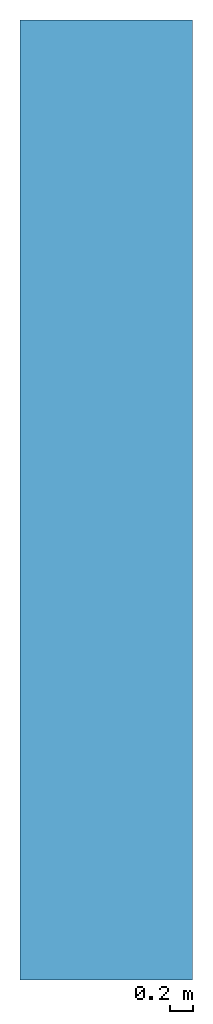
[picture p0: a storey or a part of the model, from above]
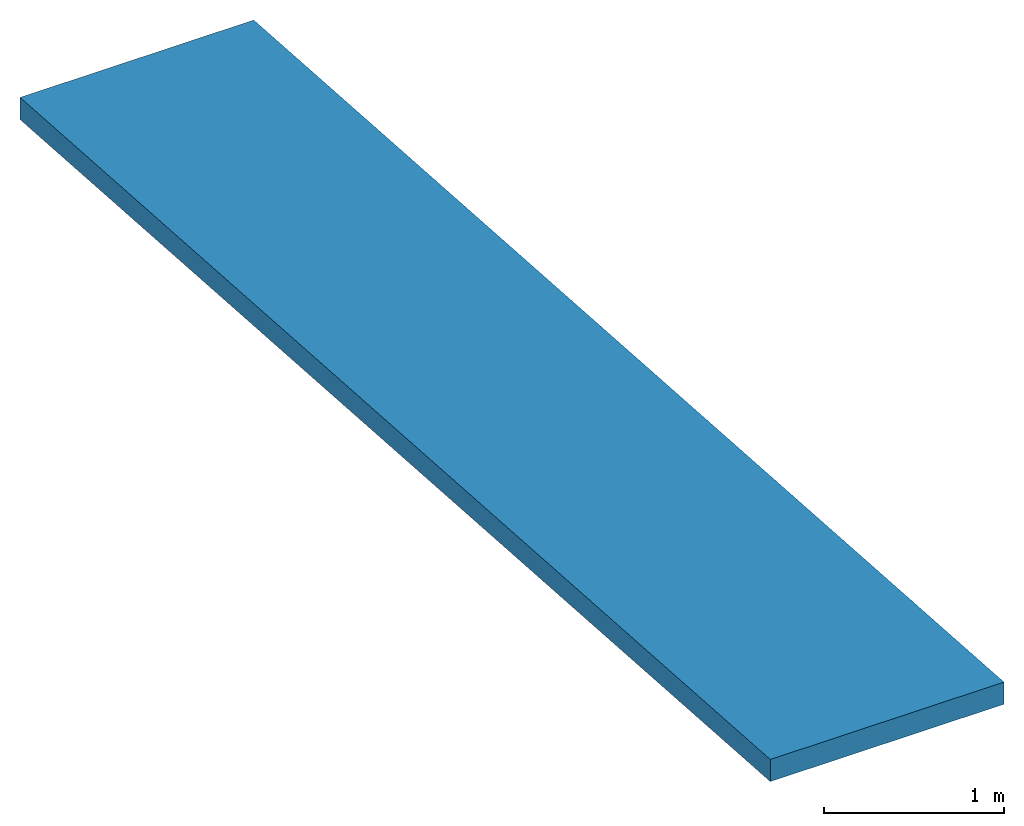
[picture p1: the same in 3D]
Properties of the parts of a building model (IFC2X3), part 1 of 3

# File
Description: ViewDefinition [CoordinationView_V2.0]
File name: Numéro du projet
Time: 2016-10-14T11:20:03
Written by: The EXPRESS Data Manager Version 5.02.0100.07 : 28 Aug 2013
Made in: 20140905_0730(x64) - Exporter 15.7.0.0 - Interface alternative d'export 15.7.0.0
Comment: STEP Physical File produced by: The EXPRESS Data Manager Version 5.02.0100.07 : 28 Aug 2013 * Module: EDMstepFileFactory/EDMstandAlone * Creation date: Fri Oct 14 11:20:03 2016 * Host: Mu-11 * Database: C:\Users\UTILIS~1\AppData\Local\Temp\{3E19F668-D2DF-4540-B0BE-C218E94157A1}\ifc * Database version: 5507 * Database creation date: Fri Oct 14 11:19:26 2016 * Schema: IFC2X3 * Model: DataRepository.ifc * Model creation date: Fri Oct 14 11:19:26 2016 * Header model: DataRepository.ifc_HeaderModel * Header model creation date: Fri Oct 14 11:19:26 2016 * EDMuser: sdai-user * EDMgroup: sdai-group * License ID and type: 5605 : Permanent license. Expiry date: * EDMstepFileFactory options: 020000

# IfcProject, Numéro du projet
LongName: Construction du Pôle Aéronautique au lycée; Phase: DCE

# IfcSite, Default
RefLatitude: 48, 51, 23, 999633; RefLongitude: 2, 21, 3, 553905; RefElevation: 0 cm

# IfcBuilding
Pset_BuildingCommon - NumberOfStoreys: 14

# IfcBuildingStorey (13)
Name | LongName | Elevation (cm)
-77 | -77 | -77
RDC | RDC | -8.82466e-11
vestiaires | vestiaires | 30
R+1 | R+1 | 343
Toiture E1 | Toiture E1 | 373
Acrotère E1 | Acrotère E1 | 410
Acrotère EXT1 | Acrotère EXT1 | 451
Toiture E2 | Toiture E2 | 715
Acrotère E2 | Acrotère E2 | 722
724 | 724 | 724
Acrotère E3 | Acrotère E3 | 801
814 | 814 | 814
Acrotère EXT2 | Acrotère EXT2 | 855

# IfcSpace (77)
InteriorOrExteriorSpace: INTERNAL
Name | In | LongName | Reference | CeilingCovering | WallCovering | FloorCovering
001 | RDC | Sas Hall | Sas Hall 001 | plaf. dalles 60x60 | mur. TV+peinture | sol. existant non modifié carrelage
026 | RDC | Bureau accueil | Bureau accueil 026 | plaf. existant non modifié dalles 60x60 | mur. TV+peinture | sol. existant non modifié moquette
025 | RDC | Réunion | Réunion 025 | plaf. existant non modifié dalles 60x60 | mur. TV+peinture | sol. existant non modifié moquette
014 | RDC | Chaufferie | Chaufferie 014 | plaf. existant non modifié flocage | mur. existant non modifié parpaing | sol. existant non modifié dalle béton
017 | RDC | Travail enseignants | Travail enseignants 017 | plaf. dalles 60x60 | mur. peinture | sol. existant non modifié dalle béton
005 | R+1 | EG/FC | EG/FC 005 | plaf. dalles 60x60 | mur. peinture | sol. pvc
002 | R+1 | Palier 01 R+1 | Palier 01 R+1 002 | dalles fibres bois 120x60 | TV+peinture | sol. pvc
009 | R+1 | Toiture Terrasse | Toiture Terrasse 009
038 | RDC | Travail élèves | Travail élèves 038 | plaf. dalles 60x60 | mur. peinture | sol. existant non modifié dalle béton
039 | RDC | Dgmt sanit. eleve | Dgmt sanit. eleve 039 | plaf. dalles 60x60 | mur. peinture | sol. carrelage
043 | RDC | Vest. H Profs | Vest. H Profs 043 | plaf. dalles 60x60 | mur. faïence | sol. carrelage
046 | RDC | Ménage | Ménage 046 | plaf. existant non modifié plâtre + peinture neuve | mur. peinture + faïence | sol. carrelage
047 | RDC | TP avionique | TP avionique 047 | plaf. dalles 60x60 | mur. peinture | sol. dalle béton
048 | RDC | TP électricité | TP électricité 048 | plaf. dalles 60x60 | mur. peinture | dalle béton + traitement surface
049 | RDC | TP moteur | TP moteur 049 | plaf. dalles 60x60 | mur. peinture | dalle béton + traitement surface
050 | RDC | Grand magasin | Grand magasin 050 | plaf. dalles 60x60 | mur. peinture | dalle béton + traitement surface
051 | RDC | Petit magasin | Petit magasin 051 | plaf. dalles 60x60 | mur. peinture | dalle béton + traitement surface
053 | RDC | Cours composite | Cours composite 053 | plaf. dalles 60x60 | mur. peinture | dalle béton + traitement surface
054 | RDC | TP structure composite | TP structure composite 054 | plaf. dalles 60x60 | mur. peinture | dalle béton + traitement surface
055 | RDC | TP structure métal 02 | TP structure métal 02 055 | plaf. dalles 60x60 | mur. peinture | dalle béton + traitement surface
056 | RDC | TP structure métal 01 | TP structure métal 01 056 | plaf. dalles 60x60 | mur. peinture | dalle béton + traitement surface
057 | RDC | Sas/Dgmt | Sas/Dgmt 057 | plaf. dalles 60x60 | mur. peinture | dalle béton + traitement surface
059 | RDC | Déchets dang. | Déchets dang. 059 | plaf. dalle béton apparente | mur. peinture | dalle béton + traitement surface
060 | RDC | Palier RDC Esc. | Palier RDC Esc. 060 | plaf. dalle béton apparente | mur. peinture | dalle béton + traitement surface
061 | RDC | Sas métal | Sas métal 061 | plaf. dalles 60x60 | mur. peinture | dalle béton + traitement surface
062 | RDC | Sas composite | Sas composite 062 | plaf. dalles 60x60 | mur. peinture | dalle béton + traitement surface
063 | RDC | Sas av./élec. | Sas av./élec. 063 | plaf. dalles 60x60 | mur. peinture | dalle béton + traitement surface
064 | R+1 | Salle classe 03 | Salle classe 03 064 | plaf. dalles 60x60 | mur. peinture | sol. pvc
065 | R+1 | Salle classe 04 | Salle classe 04 065 | plaf. dalles 60x60 | mur. peinture | sol. pvc
066 | R+1 | CAO/DAO | CAO/DAO 066 | plaf. dalles 60x60 | mur. peinture | sol. pvc
069 | R+1 | Local tech. 02 | Local tech. 02 069 | plaf. fibre de bois | mur. fibre de bois + peinture | dalle béton + traitement surface
071 | R+1 | Local tech. 01 | Local tech. 01 071 | plaf. fibre de bois | mur. fibre de bois + peinture | dalle béton + traitement surface
073 | RDC | Stock. prdts dang. | Stock. prdts dang. 073 | plaf. dalle béton apparente | mur. peinture | dalle béton + traitement surface
075 | RDC | Mach. asc. | Mach. asc. 075 | plaf. existant non modifié flocage | mur. existant non modifié parpaing | sol. existant non modifié dalle béton
076 | R+1 | Local tech. 03 | Local tech. 03 076 | plaf. bac acier | mur. peinture | sol. peinture sur plancher collaborant
078 | RDC | Vest. H Elèves 01 | Vest. H Elèves 01 078 | dalles fibres bois 60x60 | peinture sur plâtre | sol. existant non modifié dalle béton
079 | RDC | Vest. H Elèves 02 | Vest. H Elèves 02 079 | dalles fibres bois 60x60 | peinture sur plâtre | sol. pvc
080 | RDC | Vest. H Elèves 03 | Vest. H Elèves 03 080 | dalles fibres bois 60x60 | peinture sur plâtre | sol. pvc
081 | RDC | Vest. H Elèves 04 | Vest. H Elèves 04 081 | dalles fibres bois 60x60 | peinture sur plâtre | sol. pvc
083 | RDC | Atelier aéronefs extension | Atelier aéronefs extension 083 | plateaux perforés | bardage métal + peinture | dalle béton + traitement surface
087 | R+1 | Circu. R+1 Esc. | Circu. R+1 Esc. 087 | dalles fibres bois 120x60 | mur. peinture | sol. pvc
090 | R+1 | Circu. 01 R+1 | Circu. 01 R+1 090 | bac acier perforé existant | mur. peinture + panneaux fibres de bois | sol. pvc
091 | R+1 | Circu. 02 R+1 | Circu. 02 R+1 091 | bac acier perforé existant | garde-corps métalliques | sol. pvc
093 | R+1 | Circu. 04 R+1 | Circu. 04 R+1 093 | dalles fibres bois 120x60 | mur. peinture | sol. pvc
099 | RDC | Vest. H Elèves 05 | Vest. H Elèves 05 099 | dalles fibres bois 60x60 | peinture sur plâtre | sol. pvc
104 | vestiaires | Vest. H Elèves 04 | Vest. H Elèves 04 104 | plaf. dalles 60x60 | mur. peinture | sol. existant non modifié dalle béton
107 | vestiaires | Vest. H Elèves 03 | Vest. H Elèves 03 107 | plaf. dalles 60x60 | mur. peinture | sol. existant non modifié dalle béton
108 | vestiaires | Vest. H Elèves 02 | Vest. H Elèves 02 108 | plaf. dalles 60x60 | mur. peinture | sol. existant non modifié dalle béton
109 | vestiaires | Vest. H Elèves 01 | Vest. H Elèves 01 109 | plaf. dalles 60x60 | mur. peinture | sol. existant non modifié dalle béton
110 | vestiaires | Vest. F Elèves | Vest. F Elèves 110 | plaf. dalles 60x60 | mur. peinture | sol. existant non modifié dalle béton
118 | vestiaires | Sanit. H élèves 02 | Sanit. H élèves 02 118 | plaf. dalles 60x60 | mur. peinture + faïence | sol. existant non modifié dalle béton
082 | RDC | Sanit. H élèves 01 | Sanit. H élèves 01 082 | plaf. dalles 60x60 | mur. faïence | sol. carrelage
084 | RDC | Sanit. F élèves | Sanit. F élèves 084 | plaf. dalles 60x60 | mur. faïence | sol. carrelage
088 | R+1 | Local compresseur | Local compresseur 088 | plaf. fibre de bois | mur. fibre de bois | dalle béton + traitement surface
089 | RDC | Atelier aéronefs existant | Atelier aéronefs existant 089 | plaf. bac acier perforé existant | mur. bardage métal existant + peinture | sol. existant non modifié dalle béton
094 | RDC | Circu. 03 Atelier RDC | Circu. 03 Atelier RDC 094 |  | mur. medium teinté perforé + panneaux fibres de bois | dalle béton + traitement surface
097 | RDC | Circu. 02 Atelier RDC | Circu. 02 Atelier RDC 097 | dalles fibres bois 120x60 | mur. medium teinté perforé + panneaux fibres de bois | dalle béton + traitement surface
100 | RDC | Salle profs. | Salle profs. 100 | plaf. dalles 60x60 | mur. peinture | sol. dalle béton
101 | RDC | Doc. tech. | Doc. tech. 101 | plaf. dalles 60x60 | mur. peinture | sol. dalle béton
102 | RDC | Vie des élèves | Vie des élèves 102 | plaf. dalles 60x60 | mur. peinture | sol. existant non modifié dalle béton
103 | RDC | Vest. F Profs | Vest. F Profs 103 | plaf. dalles 60x60 | mur. faïence | sol. carrelage
105 | RDC | Info. | Info. 105 | plaf. placo |  | sol. carrelage
106 | RDC | Hall/Accueil | Hall/Accueil 106 | plaf. dalles 60x60 inchangées | mur. TV+peinture | sol. existant non modifié carrelage
116 | RDC | Circu. 01 Atelier RDC | Circu. 01 Atelier RDC 116 | dalles fibres bois 120x60 | mur. peinture | sol. existant non modifié dalle béton
117 | R+1 | ACT/maint. virt | ACT/maint. virt 117 | plaf. dalles 60x60 | mur. peinture | sol. pvc
120 | R+1 | Salle classe 01 | Salle classe 01 120 | plaf. dalles 60x60 | mur. peinture | sol. pvc
121 | R+1 | Salle de classe 02 | Salle de classe 02 121 | plaf. dalles 60x60 | mur. peinture | sol. pvc
122 | R+1 | Circu 03 R+1 | Circu 03 R+1 122 | plaf. charpente | mur. panneaux fibre de bois | sol. pvc
124 | R+1 | Placard 02 | Placard 02 124 | plaf. dalles 60x60 | mur. peinture | sol. pvc
125 | RDC | Placard elec 01 | Placard elec 01 125 | plaf. peinture | mur. peinture | sol. dalle béton
126 | RDC | Local déchet | Local déchet 126 | bac acier | treillis soudé | sol. dalle béton
127 | RDC | Circulation vestiaire | Circulation vestiaire 127
128 | RDC | Pl. TP elec | Pl. TP elec 128 | plaf. peinture
129 | RDC | Cfa 01 | Cfa 01 129
130 | RDC | Cfa 01 | Cfa 01 130 | plaf. peinture
131 | R+1 | Pl. Elec. 03 | Pl. Elec. 03 131 | plaf. placo
132 | R+1 | Pièce | Pièce 132 | dalles fibres bois 120x60

# IfcBeam: IPE-Poutrelles_240:IPE240:577120 (2)
In: RDC
Material: Métal - Acier - 345 MPa
Pset_BeamCommon - LoadBearing: yes; IsExternal: no; Reference: IPE240; Span: 633.9 cm; Slope: 2.19531 deg
Name (IPE-Poutrelles_240:IPE240:...)
589190
768656

# IfcBuildingElementProxy: 1000 x 800 mm (3)
In: Acrotère E1
Type - Material: Acier - Galvanisé
Pset_BuildingElementProxyCommon - Reference: 1000 x 800 mm
Name (Grille d'aération-100x80:1000 x 800 mm:...)
1417437
1754409
1755015

# IfcBuildingElementProxy: 1700 x 800 mm (4)
Type - Material: Acier - Galvanisé
Pset_BuildingElementProxyCommon - Reference: 1700 x 800 mm
Name (Grille d'aération-100x80:1700 x 800 mm:...) | In
1752096 | Acrotère E1
1881553 | RDC
1881798 | vestiaires
2003831 | Acrotère E1

# IfcBuildingElementProxy: 200 x 200 mm (3)
Type - Material: Acier - Galvanisé
Pset_BuildingElementProxyCommon - Reference: 200 x 200 mm
Name (Grille d'aération 20x20- Mur:200 x 200 mm:...) | In
1395204 | vestiaires
2146164 | Acrotère E1
2171006 | 056

# IfcBuildingElementProxy: 310x400, Grille d'aération-100x80:310x400:1752675
In: RDC
Type - Material: Acier - Galvanisé
Pset_BuildingElementProxyCommon - Reference: 310x400

# IfcBuildingElementProxy: 600mm, Echelle à crinoline - 02:600mm:1773401
In: R+1
Type - Material: Métal - Aluminium
Pset_BuildingElementProxyCommon - Reference: 600mm

# IfcBuildingElementProxy: 900 x 600 mm, Grille d'aération-100x20:900 x 600 mm:1754410
In: Acrotère E1
Type - Material: Acier - Galvanisé
Pset_BuildingElementProxyCommon - Reference: 900 x 600 mm

# IfcBuildingElementProxy: Banc_Moshi_235cm, Banc_Moshi_235cm:Banc_Moshi_235cm:1062523
In: 053
Type - Material: polantis metal, polantis wood
Pset_BuildingElementProxyCommon - Reference: Banc_Moshi_235cm

# IfcBuildingElementProxy: Garde-corps_R+1-esc-1, Garde-corps_R+1-esc-1:Garde-corps_R+1-esc-1:2020194
In: 087
Pset_BuildingElementProxyCommon - Reference: Garde-corps_R+1-esc-1

# IfcBuildingElementProxy: Multi-cyclone, Multi-cyclone:Multi-cyclone:669395
In: R+1
Type - Material: Forme par défaut
Pset_BuildingElementProxyCommon - Reference: Multi-cyclone

# IfcBuildingElementProxy: Ordinateur Mac (23)
Type - Material: Plastique - Blanc brillant, Métal - Aluminium satiné, Verre - Noir brillant
Pset_BuildingElementProxyCommon - Reference: Ordinateur Mac
Name (Ordinateur Mac:Ordinateur Mac:...) | In
1072757 | 102
1073011 | 102
1073091 | 102
1073150 | 102
1073151 | 102
1092645 | 089
1092646 | 089
1092986 | 089
1092987 | 089
1093031 | 089
1093032 | 089
1093033 | 089
1093034 | 089
1093087 | 089
1093088 | 089
1093089 | 089
1093090 | 089
1093091 | 089
1093092 | 089
1093093 | 089
1093094 | 089
1528579 | 050
1528580 | 050

# IfcBuildingElementProxy: Portique_1-2 (2)
In: RDC
Pset_BuildingElementProxyCommon - Reference: Portique_1-2
Name (Portique_11:Portique_1-2:...)
776761
776763

# IfcBuildingElementProxy: Portique_3, Portique_3:Portique_3:603496
In: RDC
Pset_BuildingElementProxyCommon - Reference: Portique_3

# IfcBuildingElementProxy: Portique_3 2, Portique_1:Portique_3 2:768664
In: RDC
Pset_BuildingElementProxyCommon - Reference: Portique_3 2

# IfcBuildingElementProxy: Portique_4-5-6 2 (3)
In: RDC
Pset_BuildingElementProxyCommon - Reference: Portique_4-5-6 2
Name (Portique_4-51:Portique_4-5-6 2:...)
768658
768660
768662

# IfcBuildingElementProxy: Portique_D-E-G (3)
In: RDC
Pset_BuildingElementProxyCommon - Reference: Portique_D-E-G
Name (Portique_D-E-G:Portique_D-E-G:...)
768680
768682
768684

# IfcBuildingElementProxy: Portique_H, Portique_H:Portique_H:768678
In: RDC
Pset_BuildingElementProxyCommon - Reference: Portique_H

# IfcBuildingElementProxy: Profil en relief:Plinthe-10x2 (5)
Pset_BuildingElementProxyCommon - Reference: Plinthe-10x2
Name (Profil en relief:...) | In
3 x Plinthe-10x2 | RDC
2 x Plinthe-10x2 | R+1

# IfcBuildingElementProxy: Profil en relief:Plinthe-carrelage-30x10
In: RDC
Pset_BuildingElementProxyCommon - Reference: Plinthe-carrelage-30x10

# IfcBuildingElementProxy: Profil en relief:Profil en relief
In: RDC
Pset_BuildingElementProxyCommon - Reference: Profil en relief

# IfcBuildingElementProxy: Profil en relief:Profil-acier-5x5 (28)
Pset_BuildingElementProxyCommon - Reference: Profil-acier-5x5
Name (Profil en relief:...) | In
10 x Profil-acier-5x5 | R+1
18 x Profil-acier-5x5 | RDC

# IfcBuildingElementProxy: Profil en relief:profil-couvertine (4)
Pset_BuildingElementProxyCommon - Reference: profil-couvertine
Name (Profil en relief:...) | In
3 x profil-couvertine | R+1
profil-couvertine | RDC

# IfcBuildingElementProxy: Profil en relief:profil-couvertine-ex (9)
Pset_BuildingElementProxyCommon - Reference: profil-couvertine-ex
Name (Profil en relief:...) | In
7 x profil-couvertine-ex | RDC
profil-couvertine-ex | R+1
profil-couvertine-ex | Toiture E1

# IfcBuildingElementProxy: descenteEP (10)
Pset_BuildingElementProxyCommon - Reference: descenteEP
Name (descenteEP:descenteEP:...) | In
1228838 | R+1
1229246 | R+1
1229569 | R+1
1229680 | R+1
1229801 | R+1
1230112 | R+1
1230804 | R+1
1231167 | R+1
1900189 | Acrotère E3
1900580 | Acrotère E2

# IfcBuildingElementProxy: ensemble-Garde-corps_R+1, ensemble-Garde-corps_R+1:ensemble-Garde-corps_R+1:1492431
In: R+1
Pset_BuildingElementProxyCommon - Reference: ensemble-Garde-corps_R+1

# IfcBuildingElementProxy: garde-corps-demontable (39)
Pset_BuildingElementProxyCommon - Reference: garde-corps-demontable
Name (garde-corps-demontable:garde-corps-demontable:...) | In
2033946 | 083
2033958 | 083
2034228 | 083
2034236 | 083
2034244 | 083
2034254 | 083
2034264 | 083
2034270 | 083
2034278 | 083
2034288 | 083
2034326 | 083
2034327 | 083
2034382 | 083
2034390 | 083
2034400 | 083
2034412 | 083
2034420 | 083
2034430 | 083
2034442 | 083
2034454 | 083
2034462 | 083
2034472 | 083
2036073 | 083
2036113 | 083
2036123 | 083
2036131 | 083
2036139 | 083
2036147 | 083
2036155 | 083
2036165 | 083
2036177 | 083
2155505 | 089 | Group: Groupe de modèles:Garde-corps:2155973
2155656 | 089 | Group: Groupe de modèles:Garde-corps:2155973
2155762 | 089 | Group: Groupe de modèles:Garde-corps:2155973
2155802 | 089 | Group: Groupe de modèles:Garde-corps:2155973
2155838 | 089 | Group: Groupe de modèles:Garde-corps:2155973
2155874 | 089 | Group: Groupe de modèles:Garde-corps:2155973
2155910 | 089 | Group: Groupe de modèles:Garde-corps:2155973
2155946 | 089 | Group: Groupe de modèles:Garde-corps:2155973

# IfcBuildingElementProxy: parevue-barreau, parevue-barreau:parevue-barreau:1796733
In: 089
Pset_BuildingElementProxyCommon - Reference: parevue-barreau

# IfcBuildingElementProxy: profil-metallique-recouvrement-JD, profil-metallique-recouvrement-JD:profil-metallique-recouvrement-JD:1324721
In: RDC
Type - Material: Montant métallique
Pset_BuildingElementProxyCommon - Reference: profil-metallique-recouvrement-JD

# IfcColumn: Diamètre de 200 mm (8)
In: RDC
Type - ElementType: Diamètre de 200 mm; PredefinedType: COLUMN; Material: Béton, coffrage en contreplaqué
Pset_ColumnCommon - LoadBearing: yes; IsExternal: no; Reference: Diamètre de 200 mm
Name
Poteau porteur rond:Diamètre de 200 mm:336266
Poteau porteur rond:Diamètre de 200 mm:337549
Poteau porteur rond:Diamètre de 200 mm:337617
Poteau porteur rond:Diamètre de 200 mm:337636
Poteau porteur rond:Diamètre de 200 mm:337651
Poteau porteur rond:Diamètre de 200 mm:337666
Poteau porteur rond:Diamètre de 200 mm:337681
Poteau porteur carre:Diamètre de 200 mm:639674

# IfcColumn: Diamètre de 200 mm (2)
In: R+1
Type - ElementType: Diamètre de 200 mm; PredefinedType: COLUMN; Material: Béton, coulé sur place, gris
Pset_ColumnCommon - LoadBearing: yes; IsExternal: no; Reference: Diamètre de 200 mm
Name (Poteau porteur rectangle:Diamètre de 200 mm:...)
1629248
1629738

# IfcColumn: Diamètre de 780 mm, Poteau porteur rond:Diamètre de 780 mm:373323
In: RDC
Type - ElementType: Diamètre de 780 mm; PredefinedType: COLUMN; Material: Maçonnerie - Béton
Pset_ColumnCommon - LoadBearing: yes; IsExternal: no; Reference: Diamètre de 780 mm

# IfcColumn: Diamètre de 800 m, Poteau porteur rond simple:Diamètre de 800 m:2145215
In: vestiaires
Type - ElementType: Diamètre de 800 m; PredefinedType: COLUMN; Material: Béton, coulé sur place
Pset_ColumnCommon - LoadBearing: yes; IsExternal: no; Reference: Diamètre de 800 m

# IfcColumn: HEA160 (9)
In: RDC
Type - ElementType: HEA160; PredefinedType: COLUMN; Material: Acier, 45-345
Pset_ColumnCommon - LoadBearing: yes; IsExternal: no; Reference: HEA160
Name
IPE-240-120:HEA160:768575
IPE-240-120:HEA160:768577
IPE-240-120:HEA160:768603
IPE-240-120:HEA160:768605
IPE-240-120:HEA160:768607
IPE-200-100:HEA160:768611
IPE-200-100:HEA160:768613
IPE-200-100:HEA160:768615
IPE-240-120:HEA160:768668

# IfcColumn: IPE 180 (48)
Type - ElementType: IPE 180; PredefinedType: COLUMN; Material: Acier, 45-345
Pset_ColumnCommon - LoadBearing: yes; IsExternal: no; Reference: IPE 180
Name (IPE-180-90:IPE 180:...) | In
397627 | RDC
400613 | RDC
745833 | R+1
745837 | R+1
745839 | R+1
745843 | R+1
746483 | R+1
746485 | R+1
746487 | R+1
746489 | R+1
768581 | RDC
768583 | RDC
768648 | RDC
1098688 | RDC
1350390 | RDC
1350392 | RDC
1370499 | R+1
1370501 | R+1
1370512 | R+1
1370514 | R+1
1792442 | RDC
1792444 | RDC
1792456 | RDC
1792458 | RDC
1792460 | RDC
1792462 | RDC
1792464 | RDC
1792466 | RDC
1792468 | RDC
1792470 | RDC
1792472 | RDC
1792474 | RDC
1792476 | RDC
1792478 | RDC
1792480 | RDC
1792482 | RDC
1792484 | RDC
1792486 | RDC
1792488 | RDC
1792490 | RDC
1792492 | RDC
1792494 | RDC
1792496 | RDC
1792498 | RDC
1792500 | RDC
1792502 | RDC
1792504 | RDC
1792506 | RDC

# IfcColumn: IPE 270 (2)
In: RDC
Type - ElementType: IPE 270; PredefinedType: COLUMN; Material: Acier, 45-345
Pset_ColumnCommon - LoadBearing: yes; IsExternal: no; Reference: IPE 270
Name (IPE-270-135:IPE 270:...)
400209
768609

# IfcColumn: IPE 300 (7)
Type - ElementType: IPE 300; PredefinedType: COLUMN; Material: Acier, 45-345
Pset_ColumnCommon - LoadBearing: yes; IsExternal: no; Reference: IPE 300
Name (IPE-300-150:IPE 300:...) | In
484381 | R+1
768569 | RDC
768571 | RDC
768573 | RDC
768644 | RDC
768646 | RDC
768650 | R+1

# IfcColumn: IPE 450 (7)
In: RDC
Type - ElementType: IPE 450; PredefinedType: COLUMN; Material: Acier, 45-345
Pset_ColumnCommon - LoadBearing: yes; IsExternal: no; Reference: IPE 450
Name
IPE-450-190:IPE 450:768585
IPE-450-190:IPE 450:768587
IPE-450-190:IPE 450:768597
IPE-450-190:IPE 450:768601
IPE-96-100:IPE 450:768670
IPE-450-190:IPE 450:1098042
IPE-450-190:IPE 450:1098044

# IfcColumn: IPE200 (4)
In: RDC
Type - ElementType: IPE200; PredefinedType: COLUMN; Material: Acier, 45-345
Pset_ColumnCommon - LoadBearing: yes; IsExternal: no; Reference: IPE200
Name (IPE-200-100:IPE200:...)
399874
400471
400545
400561

# IfcColumn: IPE240 (2)
In: RDC
Type - ElementType: IPE240; PredefinedType: COLUMN; Material: Acier, 45-345
Pset_ColumnCommon - LoadBearing: yes; IsExternal: no; Reference: IPE240
Name (IPE-240-120:IPE240:...)
387907
397541

# IfcColumn: IPE360 (7)
In: RDC
Type - ElementType: IPE360; PredefinedType: COLUMN; Material: Acier, 45-345
Pset_ColumnCommon - LoadBearing: yes; IsExternal: no; Reference: IPE360
Name (IPE-360-170:IPE360:...)
768563
768565
768567
768589
768591
768593
836311

# IfcCovering: Plafond composé:Pafond-fibre-de-bois, Plafond composé:Pafond-fibre-de-bois:2104556
In: 132
PredefinedType: CEILING; Material: Panneau de fibres à densité moyenne MDF 10 cm
Pset_CoveringCommon - Reference: Pafond-fibre-de-bois; TotalThickness: 10 cm

# IfcCovering: Plafond composé:Plafond 120x60 (3)
PredefinedType: CEILING; Material: Maçonnerie - Isolant 3 cm, Faux-plafond-Trame 60x 60_MU 2 cm
Pset_CoveringCommon - Reference: Plafond 120x60; TotalThickness: 5 cm
Name (Plafond composé:Plafond 120x60:...) | In
993673 | R+1
1398973 | RDC
2018109 | 132

# IfcCovering: Plafond composé:Plafond avec isolation (51)
PredefinedType: CEILING; Material: Maçonnerie - Isolant_MU 5 cm
Pset_CoveringCommon - Reference: Plafond avec isolation; TotalThickness: 5 cm
Name (Plafond composé:Plafond avec isolation:...) | In
992757 | RDC
992784 | RDC
992800 | RDC
992824 | 084
992838 | 084
992854 | 105
992862 | RDC
992885 | RDC
992893 | 103
992904 | RDC
992912 | RDC
992921 | RDC
992931 | RDC
992949 | RDC
992978 | RDC
993002 | RDC
993036 | RDC
993046 | 129
993057 | RDC
993083 | RDC
993117 | RDC
993138 | 118
993146 | 104
993154 | 107
993162 | 109
993170 | 110
993562 | 108
993633 | R+1
993641 | R+1
1398648 | 128
1398947 | RDC
1398959 | RDC
1399494 | RDC
1399507 | RDC
1399522 | RDC
1399539 | 101
1400398 | R+1
1400413 | 121
1400424 | 120
1400432 | 117
1404346 | R+1
1696043 | 097
1771134 | R+1
1772691 | R+1
1775926 | R+1
1778344 | RDC
1825757 | 103
1825768 | 103
1825784 | 103
1854031 | RDC
2046370 | 102

# IfcCovering: Plafond de base:Plafond 600 mm x 600 mm (2)
In: R+1
PredefinedType: CEILING
Pset_CoveringCommon - Reference: Plafond 600 mm x 600 mm
Name (Plafond de base:Plafond 600 mm x 600 mm:...)
993578
993588

# IfcCurtainWall: Mur-rideau:1 m x 1 m - Meneaux, Mur-rideau:1 m x 1 m - Meneaux:782304
In: R+1
Pset_CurtainWallCommon - IsExternal: no; Reference: 1 m x 1 m - Meneaux

# IfcCurtainWall: Mur-rideau:Simple panneau (72)
Pset_CurtainWallCommon - IsExternal: no; Reference: Simple panneau
Name (Mur-rideau:Simple panneau:...) | In | Group
693776 | RDC | Groupe de modèles:mur-rideau-1:696009
703710 | RDC | Groupe de modèles:fc-ouest-men-03:712083
709952 | RDC | Groupe de modèles:porte-pliante-16mX5m:710013
712245 | RDC | Groupe de modèles:fc-ouest-men-05:712792
712561 | RDC | Groupe de modèles:fc-ouest-men-01:712563
714304 | RDC | Groupe de modèles:fc-est-men-01:714451
717006 | RDC
733055 | R+1 | Groupe de modèles:fc-est-men-04:733328
733670 | R+1 | Groupe de modèles:fc-est-men-04:733672
734568 | R+1 | Groupe de modèles:fc-est-men-05:734619
734798 | R+1 | Groupe de modèles:fc-est-men-06:735172
734948 | R+1 | Groupe de modèles:fc-est-men-07:735197
748059 | RDC
750284 | RDC | Groupe de modèles:men-2nd-j-type3:750290
750903 | RDC | Groupe de modèles:men-2nd-j-100:750974
758243 | RDC | Groupe de modèles:men-2nd-j-100:758245
758615 | RDC | Groupe de modèles:imposte-vitree-151cm:758786
759191 | RDC | Groupe de modèles:imposte-vitree-151cm:759193
759770 | RDC | Groupe de modèles:men-2nd-j-type3:759776
759816 | RDC | Groupe de modèles:men-2nd-j-type3:759822
760032 | RDC | Groupe de modèles:men-2nd-j-type5:760064
836055 | R+1 | Groupe de modèles:men-2nd-j-100-hsup:836057
836076 | R+1 | Groupe de modèles:men-2nd-j-100-hsup:836078
836097 | R+1 | Groupe de modèles:men-2nd-j-100-hsup:836099
836132 | R+1 | Groupe de modèles:men-2nd-j-100-hsup:836134
836153 | R+1 | Groupe de modèles:men-2nd-j-100-hsup:836155
836294 | R+1 | Groupe de modèles:imposte-vitree-102cm:836300
891742 | R+1 | Groupe de modèles:imposte-vitree-102cm:891748
968480 | RDC | Groupe de modèles:imposte-vitree-204:968508
1119323 | RDC
1247236 | RDC | Groupe de modèles:imposte-vitree-102cm--:1247272
1282591 | RDC | Groupe de modèles:fc-ouest-men-04:1282593
1284019 | RDC | Groupe de modèles:fc-ouest-men-02:1284021
1284645 | RDC | Groupe de modèles:fc-ouest-men-06:1222254
1292162 | RDC
1360494 | R+1 | Groupe de modèles:shed2:1363791
1362082 | R+1 | Groupe de modèles:shed1-:1363832
1362164 | R+1
1406046 | RDC | Groupe de modèles:fc-ouest-men-04:1406048
1449844 | R+1 | Groupe de modèles:men-2nd-j-100-hsup:1449846
1526731 | RDC | Groupe de modèles:men-2nd-j-100:1526733
1604210 | RDC
1604349 | RDC
1604377 | RDC
1604395 | RDC
1604415 | RDC
1604443 | RDC
1604461 | RDC
1604822 | RDC
1607775 | RDC
1608067 | RDC
1608097 | RDC
1608115 | RDC
1608135 | RDC
1627353 | RDC
1627357 | RDC
1627361 | RDC
1629918 | R+1 | Groupe de modèles:men-2nd-j-100-hsup:1628725
1629927 | R+1 | Groupe de modèles:men-2nd-j-100-hsup:1628718
1631721 | R+1
1631751 | R+1 | Groupe de modèles:men-2nd-j-100-hsup 3:1631753
1631758 | R+1
1657073 | RDC | Groupe de modèles:imposte-vitree-191 2:1657079
1744592 | R+1
1744618 | R+1
1744644 | R+1
1745365 | R+1
1745391 | R+1
1745417 | R+1
1877801 | RDC
1878107 | RDC
1880841 | RDC

# IfcDoor: 1.00m x 2.04m, Coulissante - Apparente:1.00m x 2.04m:1238631
In: RDC
Type - OperationType: SLIDING_TO_LEFT; ParameterTakesPrecedence: no; Sizeable: no; Material: Porte - Poignée, Porte - Cadre, Porte - Panneau
Type - Coulissante - Apparente:1.00m x 2.04m:1238631 - PanelOperation: SLIDING
OverallHeight: 204 cm; OverallWidth: 103 cm
Pset_DoorCommon - IsExternal: no; Reference: 1.00m x 2.04m; ThermalTransmittance: 3.7021 kg/K/s3

# IfcDoor: 123 x 204 cm, Double(R)_bois_mu:123 x 204 cm:1194059
In: RDC
Type - OperationType: DOUBLE_DOOR_SINGLE_SWING; ParameterTakesPrecedence: no; Sizeable: no; Material: Porte - Poignée, Porte - Cadre, Porte - Panneau
Type - Double(R)_bois_mu:123 x 204 cm:1194059 - PanelOperation: SWINGING
OverallHeight: 207 cm; OverallWidth: 129 cm
Pset_DoorCommon - IsExternal: no; Reference: 123 x 204 cm; ThermalTransmittance: 3.7021 kg/K/s3

# IfcDoor: 143 x 204 cm (4)
Type - OperationType: DOUBLE_DOOR_SINGLE_SWING; ParameterTakesPrecedence: no; Sizeable: no; Material: Porte - Poignée, Porte - Cadre, Porte - Panneau
Type - Double(R)_bois_Existant_mu:143 x 204 cm:1601129 - PanelOperation: SWINGING
OverallHeight: 207 cm; OverallWidth: 149 cm
Pset_DoorCommon - IsExternal: no; Reference: 143 x 204 cm; ThermalTransmittance: 3.7021 kg/K/s3
Name (Double(R)_bois_Existant_mu:143 x 204 cm:...) | In
1601129 | RDC
1601223 | RDC
1607774 | RDC
1898730 | R+1

# IfcDoor: 143 x 204 cm (2)
In: RDC
Type - OperationType: DOUBLE_DOOR_SINGLE_SWING; ParameterTakesPrecedence: no; Sizeable: no; Material: Porte - Poignée, Porte - Cadre, Porte - Panneau
Type - Double(R)_bois_Existant_mu:143 x 204 cm:1826486 - PanelOperation: SWINGING
OverallHeight: 207 cm; OverallWidth: 149 cm
Pset_DoorCommon - IsExternal: no; Reference: 143 x 204 cm; ThermalTransmittance: 3.7021 kg/K/s3
Name (Double(R)_bois_Existant_mu:143 x 204 cm:...)
1826486
1826530

# IfcDoor: 143 x 204 cm (12)
Type - ParameterTakesPrecedence: no; Sizeable: no; Material: Aluminium-Dorma Metal-Anodized Silver, Porte - Cadre, Porte - Panneau
OverallHeight: 207 cm; OverallWidth: 149 cm
Pset_DoorCommon - IsExternal: no; Reference: 143 x 204 cm; ThermalTransmittance: 3.7021 kg/K/s3
Name (Tierce(R)_bois_mu:143 x 204 cm:...) | In
654453 | RDC
654565 | RDC
654660 | RDC
662013 | R+1
662110 | R+1
679970 | R+1
736615 | RDC
1241583 | RDC
1351042 | RDC
1631308 | R+1
1694524 | RDC
1811255 | RDC

# IfcDoor: 143 x 241 cm, Tierce(R)_bois_mu:143 x 241 cm:1754408
In: R+1
Type - ParameterTakesPrecedence: no; Sizeable: no; Material: Porte - Poignée, Porte - Cadre, Porte - Panneau
OverallHeight: 244 cm; OverallWidth: 149 cm
Pset_DoorCommon - IsExternal: no; Reference: 143 x 241 cm; ThermalTransmittance: 3.7021 kg/K/s3

# IfcDoor: 163 x 204 cm, Double(R)_bois_Existant_mu:163 x 204 cm:1601128
In: RDC
Type - OperationType: DOUBLE_DOOR_SINGLE_SWING; ParameterTakesPrecedence: no; Sizeable: no; Material: Porte - Poignée, Porte - Cadre, Porte - Panneau
Type - Double(R)_bois_Existant_mu:163 x 204 cm:1601128 - PanelOperation: SWINGING
OverallHeight: 207 cm; OverallWidth: 169 cm
Pset_DoorCommon - IsExternal: no; Reference: 163 x 204 cm; ThermalTransmittance: 3.7021 kg/K/s3

# IfcDoor: 163 x 204 cm, Double(R)_bois_mu:163 x 204 cm:1194466
In: RDC
Type - OperationType: DOUBLE_DOOR_SINGLE_SWING; ParameterTakesPrecedence: no; Sizeable: no; Material: Porte - Poignée, Porte - Cadre, Porte - Panneau
Type - Double(R)_bois_mu:163 x 204 cm:1194466 - PanelOperation: SWINGING
OverallHeight: 207 cm; OverallWidth: 169 cm
Pset_DoorCommon - IsExternal: no; Reference: 163 x 204 cm; ThermalTransmittance: 3.7021 kg/K/s3

# IfcDoor: 163 x 204 cm, Double(R)_bois_mu:163 x 204 cm:1580174
In: RDC
Type - OperationType: DOUBLE_DOOR_SINGLE_SWING; ParameterTakesPrecedence: no; Sizeable: no; Material: Porte - Poignée, Porte - Cadre, Porte - Panneau
Type - Double(R)_bois_mu:163 x 204 cm:1580174 - PanelOperation: SWINGING
OverallHeight: 207 cm; OverallWidth: 169 cm
Pset_DoorCommon - IsExternal: no; Reference: 163 x 204 cm; ThermalTransmittance: 3.7021 kg/K/s3

# IfcDoor: 183 x 204 cm, Double(R)_bois_Existant_mu:183 x 204 cm:1590367
In: RDC
Type - OperationType: DOUBLE_DOOR_SINGLE_SWING; ParameterTakesPrecedence: no; Sizeable: no; Material: Porte - Poignée, Porte - Cadre, Porte - Panneau
Type - Double(R)_bois_Existant_mu:183 x 204 cm:1590367 - PanelOperation: SWINGING
OverallHeight: 207 cm; OverallWidth: 189 cm
Pset_DoorCommon - IsExternal: no; Reference: 183 x 204 cm; ThermalTransmittance: 3.7021 kg/K/s3

# IfcDoor: 183 x 204 cm, Double(R)_bois_mu:183 x 204 cm:652799
In: RDC
Type - OperationType: DOUBLE_DOOR_SINGLE_SWING; ParameterTakesPrecedence: no; Sizeable: no; Material: Porte - Poignée, Porte - Cadre, Porte - Panneau
Type - Double(R)_bois_mu:183 x 204 cm:652799 - PanelOperation: SWINGING
OverallHeight: 207 cm; OverallWidth: 189 cm
Pset_DoorCommon - IsExternal: no; Reference: 183 x 204 cm; ThermalTransmittance: 3.7021 kg/K/s3

# IfcDoor: 183 x 204 cm, Double(R)_bois_mu:183 x 204 cm:652915
In: RDC
Type - OperationType: DOUBLE_DOOR_SINGLE_SWING; ParameterTakesPrecedence: no; Sizeable: no; Material: Porte - Poignée, Porte - Cadre, Porte - Panneau
Type - Double(R)_bois_mu:183 x 204 cm:652915 - PanelOperation: SWINGING
OverallHeight: 207 cm; OverallWidth: 189 cm
Pset_DoorCommon - IsExternal: no; Reference: 183 x 204 cm; ThermalTransmittance: 3.7021 kg/K/s3

# IfcDoor: 183 x 204 cm, Double(R)_bois_mu:183 x 204 cm:652933
In: RDC
Type - OperationType: DOUBLE_DOOR_SINGLE_SWING; ParameterTakesPrecedence: no; Sizeable: no; Material: Porte - Poignée, Porte - Cadre, Porte - Panneau
Type - Double(R)_bois_mu:183 x 204 cm:652933 - PanelOperation: SWINGING
OverallHeight: 207 cm; OverallWidth: 189 cm
Pset_DoorCommon - IsExternal: no; Reference: 183 x 204 cm; ThermalTransmittance: 3.7021 kg/K/s3

# IfcDoor: 183 x 204 cm, Double(R)_bois_mu:183 x 204 cm:654791
In: RDC
Type - OperationType: DOUBLE_DOOR_SINGLE_SWING; ParameterTakesPrecedence: no; Sizeable: no; Material: Porte - Poignée, Porte - Cadre, Porte - Panneau
Type - Double(R)_bois_mu:183 x 204 cm:654791 - PanelOperation: SWINGING
OverallHeight: 207 cm; OverallWidth: 189 cm
Pset_DoorCommon - IsExternal: no; Reference: 183 x 204 cm; ThermalTransmittance: 3.7021 kg/K/s3

# IfcDoor: 183 x 260 cm, Double(R)_bois_Existant_mu:183 x 260 cm:1608468
In: RDC
Type - OperationType: DOUBLE_DOOR_SINGLE_SWING; ParameterTakesPrecedence: no; Sizeable: no; Material: Porte - Poignée, Porte - Cadre, Porte - Panneau
Type - Double(R)_bois_Existant_mu:183 x 260 cm:1608468 - PanelOperation: SWINGING
OverallHeight: 263 cm; OverallWidth: 189 cm
Pset_DoorCommon - IsExternal: no; Reference: 183 x 260 cm; ThermalTransmittance: 3.7021 kg/K/s3

# IfcDoor: 183 x 260 cm, Double(R)_bois_Existant_mu:183 x 260 cm:1608475
In: RDC
Type - OperationType: DOUBLE_DOOR_SINGLE_SWING; ParameterTakesPrecedence: no; Sizeable: no; Material: Porte - Poignée, Porte - Cadre, Porte - Panneau
Type - Double(R)_bois_Existant_mu:183 x 260 cm:1608475 - PanelOperation: SWINGING
OverallHeight: 263 cm; OverallWidth: 189 cm
Pset_DoorCommon - IsExternal: no; Reference: 183 x 260 cm; ThermalTransmittance: 3.7021 kg/K/s3

# IfcDoor: 183 x 280 cm, Double(R)_bois_mu:183 x 280 cm:1058547
In: RDC
Type - OperationType: DOUBLE_DOOR_SINGLE_SWING; ParameterTakesPrecedence: no; Sizeable: no; Material: Porte - Poignée, Porte - Cadre, Porte - Panneau
Type - Double(R)_bois_mu:183 x 280 cm:1058547 - PanelOperation: SWINGING
OverallHeight: 279 cm; OverallWidth: 189 cm
Pset_DoorCommon - IsExternal: no; Reference: 183 x 280 cm; ThermalTransmittance: 3.7021 kg/K/s3

# IfcDoor: 30 x 204 cm (4)
Type - OperationType: SINGLE_SWING_RIGHT; ParameterTakesPrecedence: no; Sizeable: no; Material: Porte - Poignée, Porte - Cadre, Porte - Panneau
Type - Simple(R)_bois_Existant_mu:30 x 204 cm:1601230 - PanelOperation: SWINGING
OverallHeight: 207 cm; OverallWidth: 36 cm
Pset_DoorCommon - IsExternal: no; Reference: 30 x 204 cm; ThermalTransmittance: 3.7021 kg/K/s3
Name (Simple(R)_bois_Existant_mu:30 x 204 cm:...) | In
1601230 | RDC
1601231 | RDC
1898626 | R+1
1898627 | R+1

# IfcDoor: 33 x 204 cm, Simple(R)_bois_mu:33 x 204 cm:1526559
In: RDC
Type - OperationType: SINGLE_SWING_LEFT; ParameterTakesPrecedence: no; Sizeable: no; Material: Porte - Poignée, Porte - Cadre, Porte - Panneau
Type - Simple(R)_bois_mu:33 x 204 cm:1526559 - PanelOperation: SWINGING
OverallHeight: 207.5 cm; OverallWidth: 40 cm
Pset_DoorCommon - IsExternal: no; Reference: 33 x 204 cm; ThermalTransmittance: 3.7021 kg/K/s3

# IfcDoor: 83 x 204 cm, Simple(R)_bois_mu:83 x 204 cm:1592818
In: RDC
Type - OperationType: SINGLE_SWING_LEFT; ParameterTakesPrecedence: no; Sizeable: no; Material: Porte - Poignée, Porte - Cadre, Porte - Panneau
Type - Simple(R)_bois_mu:83 x 204 cm:1592818 - PanelOperation: SWINGING
OverallHeight: 207.5 cm; OverallWidth: 90 cm
Pset_DoorCommon - IsExternal: no; Reference: 83 x 204 cm; ThermalTransmittance: 3.7021 kg/K/s3

# IfcDoor: 83 x 204 cm, Simple(R)_bois_mu:83 x 204 cm:625317
In: RDC
Type - OperationType: SINGLE_SWING_RIGHT; ParameterTakesPrecedence: no; Sizeable: no; Material: Porte - Poignée, Porte - Cadre, Porte - Panneau
Type - Simple(R)_bois_mu:83 x 204 cm:625317 - PanelOperation: SWINGING
OverallHeight: 207.5 cm; OverallWidth: 90 cm
Pset_DoorCommon - IsExternal: no; Reference: 83 x 204 cm; ThermalTransmittance: 3.7021 kg/K/s3

# IfcDoor: 93 x 165 cm, Simple(R)_bois_mu:93 x 165 cm:1602234
In: RDC
Type - OperationType: SINGLE_SWING_LEFT; ParameterTakesPrecedence: no; Sizeable: no; Material: Porte - Poignée, Porte - Cadre, Porte - Panneau
Type - Simple(R)_bois_mu:93 x 165 cm:1602234 - PanelOperation: SWINGING
OverallHeight: 168.5 cm; OverallWidth: 100 cm
Pset_DoorCommon - IsExternal: no; Reference: 93 x 165 cm; ThermalTransmittance: 3.7021 kg/K/s3

# IfcDoor: 93 x 165 cm, Simple(R)_bois_mu:93 x 165 cm:1604110
In: RDC
Type - OperationType: SINGLE_SWING_LEFT; ParameterTakesPrecedence: no; Sizeable: no; Material: Porte - Poignée, Porte - Cadre, Porte - Panneau
Type - Simple(R)_bois_mu:93 x 165 cm:1604110 - PanelOperation: SWINGING
OverallHeight: 168.5 cm; OverallWidth: 100 cm
Pset_DoorCommon - IsExternal: no; Reference: 93 x 165 cm; ThermalTransmittance: 3.7021 kg/K/s3

# IfcDoor: 93 x 165 cm, Simple(R)_bois_mu:93 x 165 cm:1420771
In: 814
Type - OperationType: SINGLE_SWING_RIGHT; ParameterTakesPrecedence: no; Sizeable: no; Material: Porte - Poignée, Porte - Cadre, Porte - Panneau
Type - Simple(R)_bois_mu:93 x 165 cm:1420771 - PanelOperation: SWINGING
OverallHeight: 168.5 cm; OverallWidth: 100 cm
Pset_DoorCommon - IsExternal: no; Reference: 93 x 165 cm; ThermalTransmittance: 3.7021 kg/K/s3

# IfcDoor: 93 x 204 cm, Simple(R)_bois_Existant_mu:93 x 204 cm:1096732
In: RDC
Type - OperationType: SINGLE_SWING_LEFT; ParameterTakesPrecedence: no; Sizeable: no; Material: Porte - Poignée, Porte - Cadre, Porte - Panneau
Type - Simple(R)_bois_Existant_mu:93 x 204 cm:1096732 - PanelOperation: SWINGING
OverallHeight: 207 cm; OverallWidth: 99 cm
Pset_DoorCommon - IsExternal: no; Reference: 93 x 204 cm; ThermalTransmittance: 3.7021 kg/K/s3

# IfcDoor: 93 x 204 cm, Simple(R)_bois_Existant_mu:93 x 204 cm:1096764
In: RDC
Type - OperationType: SINGLE_SWING_LEFT; ParameterTakesPrecedence: no; Sizeable: no; Material: Porte - Poignée, Porte - Cadre, Porte - Panneau
Type - Simple(R)_bois_Existant_mu:93 x 204 cm:1096764 - PanelOperation: SWINGING
OverallHeight: 207 cm; OverallWidth: 99 cm
Pset_DoorCommon - IsExternal: no; Reference: 93 x 204 cm; ThermalTransmittance: 3.7021 kg/K/s3

# IfcDoor: 93 x 204 cm (3)
In: RDC
Type - OperationType: SINGLE_SWING_LEFT; ParameterTakesPrecedence: no; Sizeable: no; Material: Porte - Poignée, Porte - Cadre, Porte - Panneau
Type - Simple(R)_bois_Existant_mu:93 x 204 cm:1601126 - PanelOperation: SWINGING
OverallHeight: 207 cm; OverallWidth: 99 cm
Pset_DoorCommon - IsExternal: no; Reference: 93 x 204 cm; ThermalTransmittance: 3.7021 kg/K/s3
Name (Simple(R)_bois_Existant_mu:93 x 204 cm:...)
1601126
1601127
1604327

# IfcDoor: 93 x 204 cm, Simple(R)_bois_Existant_mu:93 x 204 cm:535822
In: R+1
Type - OperationType: SINGLE_SWING_LEFT; ParameterTakesPrecedence: no; Sizeable: no; Material: Porte - Poignée, Porte - Cadre, Porte - Panneau
Type - Simple(R)_bois_Existant_mu:93 x 204 cm:535822 - PanelOperation: SWINGING
OverallHeight: 207 cm; OverallWidth: 99 cm
Pset_DoorCommon - IsExternal: no; Reference: 93 x 204 cm; ThermalTransmittance: 3.7021 kg/K/s3

# IfcDoor: 93 x 204 cm, Simple(R)_bois_mu:93 x 204 cm:1058958
In: RDC
Type - OperationType: SINGLE_SWING_LEFT; ParameterTakesPrecedence: no; Sizeable: no; Material: Porte - Poignée, Porte - Cadre, Porte - Panneau
Type - Simple(R)_bois_mu:93 x 204 cm:1058958 - PanelOperation: SWINGING
OverallHeight: 207.5 cm; OverallWidth: 100 cm
Pset_DoorCommon - IsExternal: no; Reference: 93 x 204 cm; ThermalTransmittance: 3.7021 kg/K/s3

# IfcDoor: 93 x 204 cm (2)
In: RDC
Type - OperationType: SINGLE_SWING_LEFT; ParameterTakesPrecedence: no; Sizeable: no; Material: Porte - Poignée, Porte - Cadre, Porte - Panneau
Type - Simple(R)_bois_mu:93 x 204 cm:1247053 - PanelOperation: SWINGING
OverallHeight: 207.5 cm; OverallWidth: 100 cm
Pset_DoorCommon - IsExternal: no; Reference: 93 x 204 cm; ThermalTransmittance: 3.7021 kg/K/s3
Name (Simple(R)_bois_mu:93 x 204 cm:...)
1247053
1422438

# IfcDoor: 93 x 204 cm, Simple(R)_bois_mu:93 x 204 cm:1315861
In: RDC
Type - OperationType: SINGLE_SWING_LEFT; ParameterTakesPrecedence: no; Sizeable: no; Material: Porte - Poignée, Porte - Cadre, Porte - Panneau
Type - Simple(R)_bois_mu:93 x 204 cm:1315861 - PanelOperation: SWINGING
OverallHeight: 207.5 cm; OverallWidth: 100 cm
Pset_DoorCommon - IsExternal: no; Reference: 93 x 204 cm; ThermalTransmittance: 3.7021 kg/K/s3

# IfcDoor: 93 x 204 cm, Simple(R)_bois_mu:93 x 204 cm:1602317
In: RDC
Type - OperationType: SINGLE_SWING_LEFT; ParameterTakesPrecedence: no; Sizeable: no; Material: Porte - Poignée, Porte - Cadre, Porte - Panneau
Type - Simple(R)_bois_mu:93 x 204 cm:1602317 - PanelOperation: SWINGING
OverallHeight: 207.5 cm; OverallWidth: 100 cm
Pset_DoorCommon - IsExternal: no; Reference: 93 x 204 cm; ThermalTransmittance: 3.7021 kg/K/s3

# IfcDoor: 93 x 204 cm, Simple(R)_bois_mu:93 x 204 cm:1807045
In: R+1
Type - OperationType: SINGLE_SWING_LEFT; ParameterTakesPrecedence: no; Sizeable: no; Material: Porte - Poignée, Porte - Cadre, Porte - Panneau
Type - Simple(R)_bois_mu:93 x 204 cm:1807045 - PanelOperation: SWINGING
OverallHeight: 207.5 cm; OverallWidth: 100 cm
Pset_DoorCommon - IsExternal: no; Reference: 93 x 204 cm; ThermalTransmittance: 3.7021 kg/K/s3

# IfcDoor: 93 x 204 cm, Simple(R)_bois_mu:93 x 204 cm:1826600
In: RDC
Type - OperationType: SINGLE_SWING_LEFT; ParameterTakesPrecedence: no; Sizeable: no; Material: Porte - Poignée, Porte - Cadre, Porte - Panneau
Type - Simple(R)_bois_mu:93 x 204 cm:1826600 - PanelOperation: SWINGING
OverallHeight: 207.5 cm; OverallWidth: 100 cm
Pset_DoorCommon - IsExternal: no; Reference: 93 x 204 cm; ThermalTransmittance: 3.7021 kg/K/s3

# IfcDoor: 93 x 204 cm, Simple(R)_bois_mu:93 x 204 cm:2158272
In: R+1
Type - OperationType: SINGLE_SWING_LEFT; ParameterTakesPrecedence: no; Sizeable: no; Material: Porte - Poignée, Porte - Cadre, Porte - Panneau
Type - Simple(R)_bois_mu:93 x 204 cm:2158272 - PanelOperation: SWINGING
OverallHeight: 207.5 cm; OverallWidth: 100 cm
Pset_DoorCommon - IsExternal: no; Reference: 93 x 204 cm; ThermalTransmittance: 3.7021 kg/K/s3

# IfcDoor: 93 x 204 cm, Simple(R)_bois_mu:93 x 204 cm:655115
In: RDC
Type - OperationType: SINGLE_SWING_LEFT; ParameterTakesPrecedence: no; Sizeable: no; Material: Porte - Poignée, Porte - Cadre, Porte - Panneau
Type - Simple(R)_bois_mu:93 x 204 cm:655115 - PanelOperation: SWINGING
OverallHeight: 207.5 cm; OverallWidth: 100 cm
Pset_DoorCommon - IsExternal: no; Reference: 93 x 204 cm; ThermalTransmittance: 3.7021 kg/K/s3

# IfcDoor: 93 x 204 cm (2)
Type - OperationType: SINGLE_SWING_LEFT; ParameterTakesPrecedence: no; Sizeable: no; Material: Porte - Poignée, Porte - Cadre, Porte - Panneau
Type - Simple(R)_bois_mu:93 x 204 cm:667513 - PanelOperation: SWINGING
OverallHeight: 207.5 cm; OverallWidth: 100 cm
Pset_DoorCommon - IsExternal: no; Reference: 93 x 204 cm; ThermalTransmittance: 3.7021 kg/K/s3
Name (Simple(R)_bois_mu:93 x 204 cm:...) | In
667513 | R+1
686160 | RDC

# IfcDoor: 93 x 204 cm (4)
Type - OperationType: SINGLE_SWING_LEFT; ParameterTakesPrecedence: no; Sizeable: no; Material: Porte - Poignée, Porte - Cadre, Porte - Panneau
Type - Simple(R)_bois_mu:93 x 204 cm:680088 - PanelOperation: SWINGING
OverallHeight: 207.5 cm; OverallWidth: 100 cm
Pset_DoorCommon - IsExternal: no; Reference: 93 x 204 cm; ThermalTransmittance: 3.7021 kg/K/s3
Name (Simple(R)_bois_mu:93 x 204 cm:...) | In
680088 | R+1
680365 | R+1
680699 | R+1
1575722 | RDC

# IfcDoor: 93 x 204 cm (3)
In: RDC
Type - OperationType: SINGLE_SWING_LEFT; ParameterTakesPrecedence: no; Sizeable: no; Material: Porte - Poignée, Porte - Cadre, Porte - Panneau
Type - Simple(R)_bois_mu:93 x 204 cm:745103 - PanelOperation: SWINGING
OverallHeight: 207.5 cm; OverallWidth: 100 cm
Pset_DoorCommon - IsExternal: no; Reference: 93 x 204 cm; ThermalTransmittance: 3.7021 kg/K/s3
Name (Simple(R)_bois_mu:93 x 204 cm:...)
745103
745231
745301

# IfcDoor: 93 x 204 cm, Simple(R)_bois_Existant_mu:93 x 204 cm:1604328
In: RDC
Type - OperationType: SINGLE_SWING_RIGHT; ParameterTakesPrecedence: no; Sizeable: no; Material: Porte - Poignée, Porte - Cadre, Porte - Panneau
Type - Simple(R)_bois_Existant_mu:93 x 204 cm:1604328 - PanelOperation: SWINGING
OverallHeight: 207 cm; OverallWidth: 99 cm
Pset_DoorCommon - IsExternal: no; Reference: 93 x 204 cm; ThermalTransmittance: 3.7021 kg/K/s3

# IfcDoor: 93 x 204 cm, Simple(R)_bois_Existant_mu:93 x 204 cm:535820
In: R+1
Type - OperationType: SINGLE_SWING_RIGHT; ParameterTakesPrecedence: no; Sizeable: no; Material: Porte - Poignée, Porte - Cadre, Porte - Panneau
Type - Simple(R)_bois_Existant_mu:93 x 204 cm:535820 - PanelOperation: SWINGING
OverallHeight: 207 cm; OverallWidth: 99 cm
Pset_DoorCommon - IsExternal: no; Reference: 93 x 204 cm; ThermalTransmittance: 3.7021 kg/K/s3

# IfcDoor: 93 x 204 cm, Simple(R)_bois_mu:93 x 204 cm:1074168
In: RDC
Type - OperationType: SINGLE_SWING_RIGHT; ParameterTakesPrecedence: no; Sizeable: no; Material: Porte - Poignée, Porte - Cadre, Porte - Panneau
Type - Simple(R)_bois_mu:93 x 204 cm:1074168 - PanelOperation: SWINGING
OverallHeight: 207.5 cm; OverallWidth: 100 cm
Pset_DoorCommon - IsExternal: no; Reference: 93 x 204 cm; ThermalTransmittance: 3.7021 kg/K/s3

# IfcDoor: 93 x 204 cm (2)
Type - OperationType: SINGLE_SWING_RIGHT; ParameterTakesPrecedence: no; Sizeable: no; Material: Porte - Poignée, Porte - Cadre, Porte - Panneau
Type - Simple(R)_bois_mu:93 x 204 cm:1420711 - PanelOperation: SWINGING
OverallHeight: 207.5 cm; OverallWidth: 100 cm
Pset_DoorCommon - IsExternal: no; Reference: 93 x 204 cm; ThermalTransmittance: 3.7021 kg/K/s3
Name (Simple(R)_bois_mu:93 x 204 cm:...) | In
1420711 | 814
1420848 | Acrotère EXT2

# IfcDoor: 93 x 204 cm (4)
In: R+1
Type - OperationType: SINGLE_SWING_RIGHT; ParameterTakesPrecedence: no; Sizeable: no; Material: Porte - Poignée, Porte - Cadre, Porte - Panneau
Type - Simple(R)_bois_mu:93 x 204 cm:1450216 - PanelOperation: SWINGING
OverallHeight: 207.5 cm; OverallWidth: 100 cm
Pset_DoorCommon - IsExternal: no; Reference: 93 x 204 cm; ThermalTransmittance: 3.7021 kg/K/s3
Name (Simple(R)_bois_mu:93 x 204 cm:...)
1450216
1450429
1631715
2020595

# IfcDoor: 93 x 204 cm (2)
In: R+1
Type - OperationType: SINGLE_SWING_RIGHT; ParameterTakesPrecedence: no; Sizeable: no; Material: Porte - Poignée, Porte - Cadre, Porte - Panneau
Type - Simple(R)_bois_mu:93 x 204 cm:1629852 - PanelOperation: SWINGING
OverallHeight: 207.5 cm; OverallWidth: 100 cm
Pset_DoorCommon - IsExternal: no; Reference: 93 x 204 cm; ThermalTransmittance: 3.7021 kg/K/s3
Name (Simple(R)_bois_mu:93 x 204 cm:...)
1629852
1631307

# IfcDoor: 93 x 204 cm, Simple(R)_bois_mu:93 x 204 cm:1807090
In: R+1
Type - OperationType: SINGLE_SWING_RIGHT; ParameterTakesPrecedence: no; Sizeable: no; Material: Porte - Poignée, Porte - Cadre, Porte - Panneau
Type - Simple(R)_bois_mu:93 x 204 cm:1807090 - PanelOperation: SWINGING
OverallHeight: 207.5 cm; OverallWidth: 100 cm
Pset_DoorCommon - IsExternal: no; Reference: 93 x 204 cm; ThermalTransmittance: 3.7021 kg/K/s3

# IfcDoor: 93 x 204 cm, Simple(R)_bois_mu:93 x 204 cm:654679
In: RDC
Type - OperationType: SINGLE_SWING_RIGHT; ParameterTakesPrecedence: no; Sizeable: no; Material: Porte - Poignée, Porte - Cadre, Porte - Panneau
Type - Simple(R)_bois_mu:93 x 204 cm:654679 - PanelOperation: SWINGING
OverallHeight: 207.5 cm; OverallWidth: 100 cm
Pset_DoorCommon - IsExternal: no; Reference: 93 x 204 cm; ThermalTransmittance: 3.7021 kg/K/s3

# IfcDoor: 93 x 204 cm (2)
Type - OperationType: SINGLE_SWING_RIGHT; ParameterTakesPrecedence: no; Sizeable: no; Material: Porte - Poignée, Porte - Cadre, Porte - Panneau
Type - Simple(R)_bois_mu:93 x 204 cm:679865 - PanelOperation: SWINGING
OverallHeight: 207.5 cm; OverallWidth: 100 cm
Pset_DoorCommon - IsExternal: no; Reference: 93 x 204 cm; ThermalTransmittance: 3.7021 kg/K/s3
Name (Simple(R)_bois_mu:93 x 204 cm:...) | In
679865 | R+1
686112 | RDC

# IfcDoor: 93 x 204 cm (3)
In: RDC
Type - OperationType: SINGLE_SWING_RIGHT; ParameterTakesPrecedence: no; Sizeable: no; Material: Porte - Poignée, Porte - Cadre, Porte - Panneau
Type - Simple(R)_bois_mu:93 x 204 cm:744287 - PanelOperation: SWINGING
OverallHeight: 207.5 cm; OverallWidth: 100 cm
Pset_DoorCommon - IsExternal: no; Reference: 93 x 204 cm; ThermalTransmittance: 3.7021 kg/K/s3
Name (Simple(R)_bois_mu:93 x 204 cm:...)
744287
744685
744851

# IfcDoor: 93 x 204 cm, Simple(R)_bois_mu:93 x 204 cm:746526
In: R+1
Type - OperationType: SINGLE_SWING_RIGHT; ParameterTakesPrecedence: no; Sizeable: no; Material: Porte - Poignée, Porte - Cadre, Porte - Panneau
Type - Simple(R)_bois_mu:93 x 204 cm:746526 - PanelOperation: SWINGING
OverallHeight: 207.5 cm; OverallWidth: 100 cm
Pset_DoorCommon - IsExternal: no; Reference: 93 x 204 cm; ThermalTransmittance: 3.7021 kg/K/s3

# IfcDoor: 93x204cm_MU, Simple(R)-bois_MU:93x204cm_MU:1590114
In: RDC
Type - OperationType: SINGLE_SWING_LEFT; ParameterTakesPrecedence: no; Sizeable: no; Material: Porte-Poignée_MU, Porte-Cadre_MU, Porte Panneau_MU
Type - Simple(R)-bois_MU:93x204cm_MU:1590114 - PanelOperation: SWINGING
OverallHeight: 207 cm; OverallWidth: 99 cm
Pset_DoorCommon - IsExternal: no; Reference: 93x204cm_MU; FireRating: CF : durée à définir; ThermalTransmittance: 3.7021 kg/K/s3
Pset_ManufacturerTypeInformation - Manufacturer: Mûrisserie Architecture

# IfcDoor: 93x204cm_MU (2)
In: RDC
Type - OperationType: SINGLE_SWING_LEFT; ParameterTakesPrecedence: no; Sizeable: no; Material: Porte-Poignée_MU, Porte-Cadre_MU, Porte Panneau_MU
Type - Simple(R)-bois_MU:93x204cm_MU:363116 - PanelOperation: SWINGING
OverallHeight: 207 cm; OverallWidth: 99 cm
Pset_DoorCommon - IsExternal: no; Reference: 93x204cm_MU; FireRating: CF : durée à définir; ThermalTransmittance: 3.7021 kg/K/s3
Pset_ManufacturerTypeInformation - Manufacturer: Mûrisserie Architecture
Name (Simple(R)-bois_MU:93x204cm_MU:...)
363116
1602313

# IfcDoor: 93x204cm_MU (2)
In: RDC
Type - OperationType: SINGLE_SWING_LEFT; ParameterTakesPrecedence: no; Sizeable: no; Material: Porte-Poignée_MU, Porte-Cadre_MU, Porte Panneau_MU
Type - Simple(R)-bois_MU:93x204cm_MU:637686 - PanelOperation: SWINGING
OverallHeight: 207 cm; OverallWidth: 99 cm
Pset_DoorCommon - IsExternal: no; Reference: 93x204cm_MU; FireRating: CF : durée à définir; ThermalTransmittance: 3.7021 kg/K/s3
Pset_ManufacturerTypeInformation - Manufacturer: Mûrisserie Architecture
Name (Simple(R)-bois_MU:93x204cm_MU:...)
637686
1574024

# IfcDoor: 93x204cm_MU (2)
In: RDC
Type - OperationType: SINGLE_SWING_RIGHT; ParameterTakesPrecedence: no; Sizeable: no; Material: Porte-Poignée_MU, Porte-Cadre_MU, Porte Panneau_MU
Type - Simple(R)-bois_MU:93x204cm_MU:363062 - PanelOperation: SWINGING
OverallHeight: 207 cm; OverallWidth: 99 cm
Pset_DoorCommon - IsExternal: no; Reference: 93x204cm_MU; FireRating: CF : durée à définir; ThermalTransmittance: 3.7021 kg/K/s3
Pset_ManufacturerTypeInformation - Manufacturer: Mûrisserie Architecture
Name (Simple(R)-bois_MU:93x204cm_MU:...)
363062
363128

# IfcDoor: 93x204cm_MU (4)
In: RDC
Type - OperationType: SINGLE_SWING_RIGHT; ParameterTakesPrecedence: no; Sizeable: no; Material: Porte-Poignée_MU, Porte-Cadre_MU, Porte Panneau_MU
Type - Simple(R)-bois_MU:93x204cm_MU:624751 - PanelOperation: SWINGING
OverallHeight: 207 cm; OverallWidth: 99 cm
Pset_DoorCommon - IsExternal: no; Reference: 93x204cm_MU; FireRating: CF : durée à définir; ThermalTransmittance: 3.7021 kg/K/s3
Pset_ManufacturerTypeInformation - Manufacturer: Mûrisserie Architecture
Name (Simple(R)-bois_MU:93x204cm_MU:...)
624751
628259
1575715
1575716

# IfcDoor: Schueco ADS 75 HD HI double-leaf outward-opening double glass 32mm, Schueco ADS 75 HD HI double-leaf outward-opening double glass 32mm:Schueco ADS 75 HD HI double-leaf outward-opening double glass 32mm:693207
In: RDC
Type - ParameterTakesPrecedence: no; Sizeable: no; Material: Alu, Glas
OverallHeight: 282 cm; OverallWidth: 202 cm
Pset_DoorCommon - IsExternal: no; Reference: Schueco ADS 75 HD HI double-leaf outward-opening double glass 32mm
Pset_ManufacturerTypeInformation - Manufacturer: Schueco International KG

# IfcFlowTerminal: #01 (4)
Material: Métal - Chrome
Pset_DistributionFlowElementCommon - Reference: #01
Name (Robinet mural - Lavabo:#01:...) | In
1264405 | Acrotère E3
1280054 | 126
1281320 | vestiaires
1979764 | Acrotère EXT2

# IfcFlowTerminal: 1 (5)
Pset_DistributionFlowElementCommon - Reference: 1
Name (Receveur de douche:1:...) | In
849670 | 043
849907 | 082
851068 | 103
1575727 | 084
1582530 | 099

# IfcFlowTerminal: 500mm x 500mm, Lavabo mural - 02:500mm x 500mm:1211703
In: 099
Material: Porcelaine - Blanche
Pset_DistributionFlowElementCommon - Reference: 500mm x 500mm

# IfcFlowTerminal: 510 mmx455 mm (4)
Pset_DistributionFlowElementCommon - Reference: 510 mmx455 mm
Name (Evier - Professionnel:510 mmx455 mm:...) | In
1276863 | 046
1375038 | 089
2002462 | 055
2169001 | 056

# IfcFlowTerminal: 550 x 360mm (7)
Material: Porcelaine - Blanche, Métal - Alu brossé
Pset_DistributionFlowElementCommon - Reference: 550 x 360mm
Name (WC suspendu - 01:550 x 360mm:...) | In
842872 | 082
843157 | 082
844348 | 043
844560 | 103
1574816 | 099
1575726 | 084
1879974 | 084

# IfcFlowTerminal: H (5)
Material: Peinture - Blanc
Pset_DistributionFlowElementCommon - Reference: H
Name (Barre d'appui - Horizontale:H:...) | In
1256252 | 082
1256343 | 043
1256371 | 103
1694214 | 099
1825714 | vestiaires

# IfcFlowTerminal: Typ 1 (5)
Classification: D2010400 Sinks (Uniformat); Material: Stahl, verchromt
Pset_ManufacturerTypeInformation - Manufacturer: Duravit
Pset_DistributionFlowElementCommon - Reference: Typ 1
Name (071150:Typ 1:...) | In
1516042 | 103
1516101 | 082
1574894 | 099
2005075 | 084
2005156 | 043

# IfcFlowTerminal: Urinoir (6)
Material: Métal - Chrome poli, Porcelaine - Blanche
Pset_DistributionFlowElementCommon - Reference: Urinoir
Name (Urinoir:Urinoir:...) | In
1133649 | 082
1135034 | 082
1135071 | 082
1575303 | 099
1575305 | 099
1575307 | 099

# IfcFurnishingElement: 100 x 100 (39)
Type - ElementType: 100 x 100; Material: Plastique - Noir, Peinture - Rouge, Bois - Mélaminé beige
Name | In
Table100x100:100 x 100:1052255 | 049
Table100x100:100 x 100:1052467 | 049
Table100x100:100 x 100:1052487 | 049
Table100x100:100 x 100:1052564 | 049
Table100x100:100 x 100:1052565 | 049
Table100x100:100 x 100:1052566 | 049
Table100x100:100 x 100:1052588 | 049
Table100x100:100 x 100:1052589 | 049
Table100x100:100 x 100:1052590 | 049
Table150x75:100 x 100:1069175 | 056
Table150x75:100 x 100:1069534 | 056
Table150x75:100 x 100:1069579 | 056
Table150x75:100 x 100:1069580 | 056
Table150x75:100 x 100:1069665 | 056
Table150x75:100 x 100:1069666 | 056
Table150x75:100 x 100:1069667 | 056
Table150x75:100 x 100:1069668 | 056
Table150x75:100 x 100:1069721 | 056
Table150x75:100 x 100:1069722 | 056
Table150x75:100 x 100:1069723 | 056
Table150x75:100 x 100:1069724 | 056
Table150x75:100 x 100:1069867 | 056
Table150x75:100 x 100:1069868 | 056
Table150x75:100 x 100:1069946 | 056
Table150x75:100 x 100:1070073 | 055
Table150x75:100 x 100:1070074 | 055
Table150x75:100 x 100:1070075 | 055
Table150x75:100 x 100:1070076 | 055
Table150x75:100 x 100:1070077 | 055
Table150x75:100 x 100:1070078 | 055
Table150x75:100 x 100:1070079 | 055
Table150x75:100 x 100:1070080 | 055
Table150x75:100 x 100:1070081 | 055
Table150x75:100 x 100:1070082 | 055
Table150x75:100 x 100:1070083 | 055
Table150x75:100 x 100:1070084 | 055
Table150x75:100 x 100:1070221 | 055
Table150x75:100 x 100:1070222 | 055
Table150x75:100 x 100:1070298 | 055

# IfcFurnishingElement: 100 x 60 (190)
Type - ElementType: 100 x 60; Material: Peinture - Rouge, Plastique - Noir, Bois - Mélaminé beige
Name | In
Table100x60+chaise:100 x 60:891644 | 038
Table100x60+chaise:100 x 60:891645 | 038
Table100x60+chaise:100 x 60:891646 | 038
Table100x60+chaise:100 x 60:891647 | 038
Table100x60+chaise:100 x 60:891648 | 038
Table100x60+chaise:100 x 60:891649 | 038
Table100x60+chaise:100 x 60:891650 | 038
Table100x60+chaise:100 x 60:891651 | 038
Table100x60+chaise:100 x 60:891652 | 038
Table100x60+chaise:100 x 60:891653 | 038
Table100x60+chaise:100 x 60:891654 | 038
Table100x60+chaise:100 x 60:891655 | 038
Table100x60+chaise:100 x 60:891656 | 038
Table100x60+chaise:100 x 60:891657 | 038
Table100x60+chaise:100 x 60:891658 | 038
Table100x60+chaise:100 x 60:891659 | 038
Table100x60+chaise:100 x 60:891660 | 038
Table100x60+chaise:100 x 60:891661 | 038
Table100x60+chaise:100 x 60:891662 | 038
Table100x60+chaise:100 x 60:891663 | 038
Table100x60+chaise:100 x 60:891664 | 038
Table100x60+chaise:100 x 60:891665 | 038
Table100x60+chaise:100 x 60:891666 | 038
Table100x60+chaise:100 x 60:891667 | 038
Table100x60+chaise:100 x 60:891792 | 065
Table100x60+chaise:100 x 60:891793 | 065
Table100x60+chaise:100 x 60:891794 | 065
Table100x60+chaise:100 x 60:891795 | 065
Table100x60+chaise:100 x 60:891796 | 065
Table100x60+chaise:100 x 60:891797 | 065
Table100x60+chaise:100 x 60:891798 | 065
Table100x60+chaise:100 x 60:891799 | 065
Table100x60+chaise:100 x 60:891800 | 065
Table100x60+chaise:100 x 60:891801 | 065
Table100x60+chaise:100 x 60:891802 | 065
Table100x60+chaise:100 x 60:891803 | 065
Table100x60+chaise:100 x 60:891804 | 065
Table100x60+chaise:100 x 60:891805 | 065
Table100x60+chaise:100 x 60:891806 | 065
Table100x60+chaise:100 x 60:891807 | 065
Table100x60+chaise:100 x 60:891808 | 065
Table100x60+chaise:100 x 60:891809 | 065
Table100x60+chaise:100 x 60:891810 | 065
Table100x60+chaise:100 x 60:891811 | 065
Table100x60+chaise:100 x 60:891812 | 065
Table100x60+chaise:100 x 60:891813 | 065
Table100x60+chaise:100 x 60:891814 | 065
Table100x60+chaise:100 x 60:891815 | 065
Table100x60+chaise:100 x 60:891818 | 064
Table100x60+chaise:100 x 60:891819 | 064
Table100x60+chaise:100 x 60:891820 | 064
Table100x60+chaise:100 x 60:891821 | 064
Table100x60+chaise:100 x 60:891822 | 064
Table100x60+chaise:100 x 60:891823 | 064
Table100x60+chaise:100 x 60:891824 | 064
Table100x60+chaise:100 x 60:891825 | 064
Table100x60+chaise:100 x 60:891826 | 064
Table100x60+chaise:100 x 60:891827 | 064
Table100x60+chaise:100 x 60:891828 | 064
Table100x60+chaise:100 x 60:891829 | 064
Table100x60+chaise:100 x 60:891830 | 064
Table100x60+chaise:100 x 60:891831 | 064
Table100x60+chaise:100 x 60:891832 | 064
Table100x60+chaise:100 x 60:891833 | 064
Table100x60+chaise:100 x 60:891834 | 064
Table100x60+chaise:100 x 60:891835 | 064
Table100x60+chaise:100 x 60:891836 | 064
Table100x60+chaise:100 x 60:891837 | 064
Table100x60+chaise:100 x 60:891838 | 064
Table100x60+chaise:100 x 60:891839 | 064
Table100x60+chaise:100 x 60:891840 | 064
Table100x60+chaise:100 x 60:891841 | 064
Table100x60+chaise:100 x 60:891906 | 005
Table100x60+chaise:100 x 60:891907 | 005
Table100x60+chaise:100 x 60:891908 | 005
Table100x60+chaise:100 x 60:891909 | 005
Table100x60+chaise:100 x 60:891910 | 005
Table100x60+chaise:100 x 60:891911 | 005
Table100x60+chaise:100 x 60:891912 | 005
Table100x60+chaise:100 x 60:891913 | 005
Table100x60+chaise:100 x 60:891914 | 005
Table100x60+chaise:100 x 60:891915 | 005
Table100x60+chaise:100 x 60:891916 | 005
Table100x60+chaise:100 x 60:891917 | 005
Table100x60+chaise:100 x 60:891918 | 005
Table100x60+chaise:100 x 60:891919 | 005
Table100x60+chaise:100 x 60:891920 | 005
Table100x60+chaise:100 x 60:891921 | 005
Table100x60+chaise:100 x 60:891922 | 005
Table100x60+chaise:100 x 60:891923 | 005
Table100x60+chaise:100 x 60:891924 | 005
Table100x60+chaise:100 x 60:891925 | 005
Table100x60+chaise:100 x 60:891926 | 005
Table100x60+chaise:100 x 60:891927 | 005
Table100x60+chaise:100 x 60:891928 | 005
Table100x60+chaise:100 x 60:891929 | 005
Table100x60+chaise:100 x 60:904424 | 047
Table100x60+chaise:100 x 60:904425 | 064
Table100x60+chaise:100 x 60:904426 | 065
Table100x60+chaise:100 x 60:904428 | 005
Table80x60+chaise:100 x 60:1066384 | 056
Table80x60+chaise:100 x 60:1066665 | 056
Table80x60+chaise:100 x 60:1066718 | 056
Table80x60+chaise:100 x 60:1066719 | 056
Table80x60+chaise:100 x 60:1066742 | 056
Table80x60+chaise:100 x 60:1066743 | 056
Table80x60+chaise:100 x 60:1066765 | 056
Table80x60+chaise:100 x 60:1066766 | 056
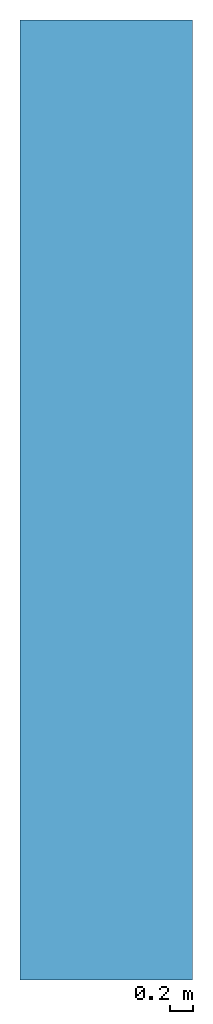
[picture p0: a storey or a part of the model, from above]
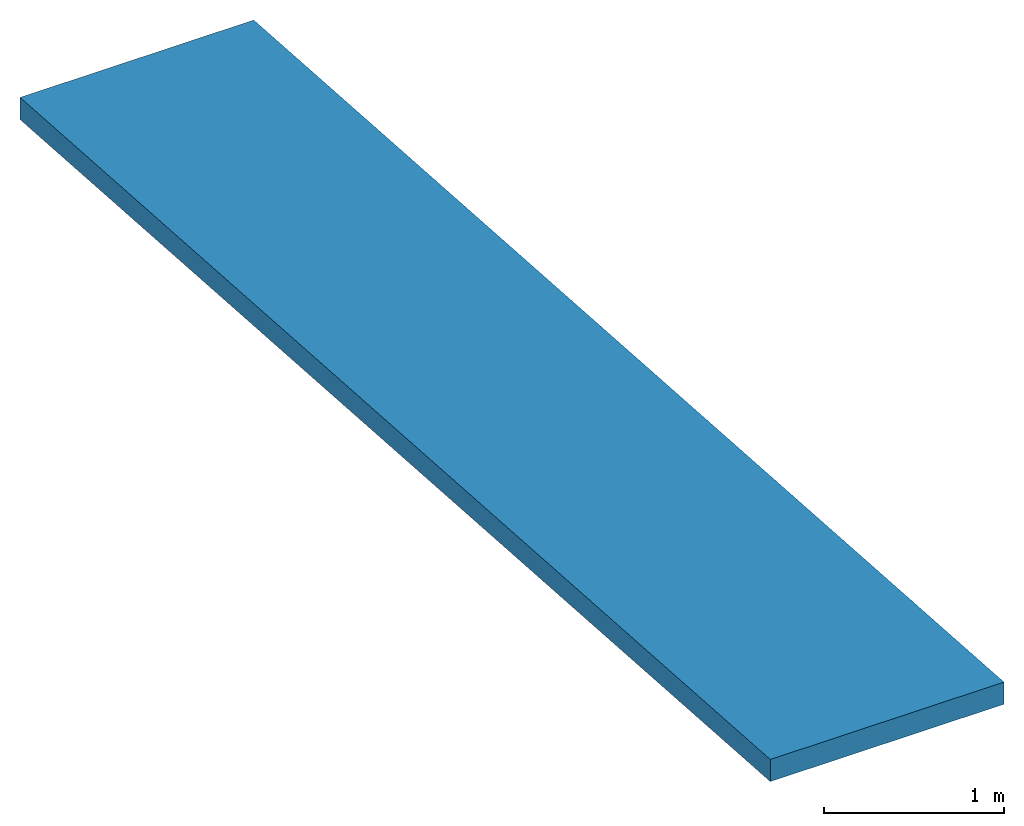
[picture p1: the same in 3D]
Properties of the parts of a building model (IFC2X3), part 2 of 3

# IfcFurnishingElement: 100 x 60 (190)
Name | In
Table80x60+chaise:100 x 60:1066806 | 056
Table80x60+chaise:100 x 60:1066807 | 056
Table80x60+chaise:100 x 60:1066884 | 053
Table80x60+chaise:100 x 60:1066885 | 053
Table80x60+chaise:100 x 60:1066886 | 053
Table80x60+chaise:100 x 60:1066887 | 053
Table80x60+chaise:100 x 60:1066888 | 053
Table80x60+chaise:100 x 60:1066889 | 053
Table80x60+chaise:100 x 60:1066890 | 053
Table80x60+chaise:100 x 60:1066891 | 053
Table80x60+chaise:100 x 60:1066892 | 053
Table80x60+chaise:100 x 60:1066893 | 053
Table80x60+chaise:100 x 60:1066894 | 053
Table80x60+chaise:100 x 60:1066895 | 053
Table80x60+chaise:100 x 60:1066896 | 053
Table80x60+chaise:100 x 60:1066897 | 053
Table80x60+chaise:100 x 60:1067400 | 056
Table80x60+chaise:100 x 60:1067401 | 056
Table80x60+chaise:100 x 60:1067402 | 056
Table80x60+chaise:100 x 60:1067403 | 056
Table80x60+chaise:100 x 60:1067404 | 056
Table80x60+chaise:100 x 60:1070422 | 053
Table300x80+2chaises:100 x 60:1079093 | 089
Table300x80+2chaises:100 x 60:1079239 | 089
Table300x80+2chaises:100 x 60:1079306 | 089
Table300x80+2chaises:100 x 60:1079307 | 089
Table300x80+2chaises:100 x 60:1079411 | 089
Table300x80+2chaises:100 x 60:1079412 | 089
Table300x80+2chaises:100 x 60:1079455 | 089
Table300x80+2chaises:100 x 60:1079456 | 089
Table100x60+chaise:100 x 60:1614209 | 066
Table100x60+chaise:100 x 60:1631369 | 117
Table100x60+chaise:100 x 60:1631727 | 120
Table100x60+chaise:100 x 60:1631728 | 120
Table100x60+chaise:100 x 60:1631729 | 120
Table100x60+chaise:100 x 60:1631730 | 120
Table100x60+chaise:100 x 60:1631731 | 120
Table100x60+chaise:100 x 60:1631732 | 120
Table100x60+chaise:100 x 60:1631733 | 120
Table100x60+chaise:100 x 60:1631734 | 120
Table100x60+chaise:100 x 60:1631735 | 120
Table100x60+chaise:100 x 60:1631736 | 120
Table100x60+chaise:100 x 60:1631737 | 120
Table100x60+chaise:100 x 60:1631738 | 120
Table100x60+chaise:100 x 60:1631739 | 120
Table100x60+chaise:100 x 60:1631740 | 120
Table100x60+chaise:100 x 60:1631741 | 120
Table100x60+chaise:100 x 60:1631742 | 120
Table100x60+chaise:100 x 60:1631743 | 120
Table100x60+chaise:100 x 60:1631744 | 120
Table100x60+chaise:100 x 60:1631745 | 120
Table100x60+chaise:100 x 60:1631746 | 120
Table100x60+chaise:100 x 60:1631747 | 120
Table100x60+chaise:100 x 60:1631748 | 120
Table100x60+chaise:100 x 60:1631749 | 120
Table100x60+chaise:100 x 60:1631750 | 120
Table100x60+chaise:100 x 60:1631769 | 121
Table100x60+chaise:100 x 60:1631770 | 121
Table100x60+chaise:100 x 60:1631771 | 121
Table100x60+chaise:100 x 60:1631772 | 121
Table100x60+chaise:100 x 60:1631773 | 121
Table100x60+chaise:100 x 60:1631774 | 121
Table100x60+chaise:100 x 60:1631775 | 121
Table100x60+chaise:100 x 60:1631776 | 121
Table100x60+chaise:100 x 60:1631777 | 121
Table100x60+chaise:100 x 60:1631778 | 121
Table100x60+chaise:100 x 60:1631779 | 121
Table100x60+chaise:100 x 60:1631780 | 121
Table100x60+chaise:100 x 60:1631781 | 121
Table100x60+chaise:100 x 60:1631782 | 121
Table100x60+chaise:100 x 60:1631783 | 121
Table100x60+chaise:100 x 60:1631784 | 121
Table100x60+chaise:100 x 60:1631785 | 121
Table100x60+chaise:100 x 60:1631786 | 121
Table100x60+chaise:100 x 60:1631787 | 121
Table100x60+chaise:100 x 60:1631788 | 121
Table100x60+chaise:100 x 60:1631789 | 121
Table100x60+chaise:100 x 60:1631790 | 121
Table100x60+chaise:100 x 60:1631791 | 121
Table100x60+chaise:100 x 60:1631792 | 121
Table100x60+chaise:100 x 60:1631794 | 121
Table100x60+chaise:100 x 60:1631795 | 120

# IfcFurnishingElement: 120 x 100 (11)
Type - ElementType: 120 x 100; Material: Métal - Aluminium, Tableau - Vert
Name (panneay-120x100:120 x 100:...) | In
916530 | 117
916566 | 064
916629 | 065
924566 | 025
924622 | 025
924765 | 026
931029 | 049
1476305 | 106
1628730 | 005
1631796 | 121
1631797 | 120

# IfcFurnishingElement: 120 x 80 (20)
Type - ElementType: 120 x 80; Material: Peinture - Rouge, Plastique - Noir, Bois - Mélaminé beige
Name (Table120x80+2chaises:120 x 80:...) | In
1614060 | 066
1614061 | 066
1614062 | 066
1614063 | 066
1614064 | 066
1614065 | 066
1614066 | 066
1614067 | 066
1631361 | 117
1631362 | 117
1631363 | 117
1631364 | 117
1631365 | 117
1631366 | 117
1631367 | 117
1631368 | 117
2158227 | 066
2158228 | 066
2158229 | 066
2158230 | 066

# IfcFurnishingElement: 1200 mm x 450 mm (5)
Type - ElementType: 1200 mm x 450 mm; Material: Bois - Mélaminé beige, Peinture - Noir, Plastique - Noir
Name (Armoire - 2 portes:1200 mm x 450 mm:...) | In
924830 | 026
1614068 | 066
1614069 | 066
1631370 | 117
1631371 | 117

# IfcFurnishingElement: 135 x 85 x 75 cm - Panneau (3)
In: 025
Type - ElementType: 135 x 85 x 75 cm - Panneau; Material: Plastique - Noir, Métal - Chrome, Aggloméré - Marron foncé brillant
Name (Table de cuisine:135 x 85 x 75 cm - Panneau:...)
923765
924159
924195

# IfcFurnishingElement: 140 x 70 (15)
In: 048
Type - ElementType: 140 x 70; Material: Plastique - Noir, Peinture - Rouge, Bois - Mélaminé beige
Name (Table140x70:140 x 70:...)
1007043
1007044
1007045
1007046
1007047
1007048
1007049
1007050
1007051
1007052
1007053
1007054
1007055
1007056
1007057

# IfcFurnishingElement: 150 x 50 x 200 (28)
Type - ElementType: 150 x 50 x 200; Material: Alu
Name (Etagère:150 x 50 x 200:...) | In
1527276 | 050
1527621 | 050
1527640 | 050
1527659 | 050
1527678 | 050
1527697 | 050
1527989 | 051
1527990 | 051
1527991 | 051
1527992 | 051
1527993 | 051
1527994 | 051
1528053 | 049
1528054 | 049
1528189 | 050
1528190 | 050
1528221 | 050
1528222 | 050
1528275 | 050
1528276 | 050
1528330 | 050
1528331 | 050
1565366 | 073
1565367 | 073
1565405 | 073
1565518 | 073
1565585 | 059
1565586 | 059

# IfcFurnishingElement: 1800 mm x 1000 mm - Luminaire (16)
Type - ElementType: 1800 mm x 1000 mm - Luminaire; Material: Métal - Aluminium, Tableau - Vert
Name (Tableau-mural-triptyque:1800 mm x 1000 mm - Luminaire:...) | In
907432 | 038
907434 | 047
907436 | 048
907438 | 049
907439 | 053
907440 | 056
907441 | 064
907442 | 065
907444 | 005
1566922 | 054
1614437 | 066
1631360 | 117
1631767 | 121
1631768 | 120
1874360 | 094
2049831 | 083

# IfcFurnishingElement: 200 x 100 (8)
In: 047
Type - ElementType: 200 x 100; Material: Peinture - Rouge, Plastique - Noir, Bois - Mélaminé beige
Name (Table200x100+2chaises:200 x 100:...)
893488
893489
893490
893491
893492
893493
893494
893495

# IfcFurnishingElement: 200 x 100 (3)
In: 005
Type - ElementType: 200 x 100; Material: Plastique - Noir, Peinture - Rouge, Bois - Mélaminé beige
Name (Table200x100:200 x 100:...)
913991
914228
914365

# IfcFurnishingElement: 2000 x 1200 mm, Bureau d'angle - 01:2000 x 1200 mm:926240
In: 026
Type - ElementType: 2000 x 1200 mm; Material: Plastique - Noir, Métal - Chrome, Bois - Bouleau

# IfcFurnishingElement: 45 x 50 x 77 cm - Blanc (14)
Type - ElementType: 45 x 50 x 77 cm - Blanc; Material: Métal - Chrome, Plastique - Noir, Cuir - Blanc
Name (Chaise:45 x 50 x 77 cm - Blanc:...) | In
924244 | 025
924334 | 025
924360 | 025
924361 | 025
924380 | 025
924381 | 025
924382 | 025
924383 | 025
924393 | 025
924394 | 025
924395 | 025
924396 | 025
927198 | 026
927294 | 026

# IfcFurnishingElement: Avec réservation pour évier (3)
Type - ElementType: Avec réservation pour évier; Material: Bois - Mélaminé jaune pastel
Name (PTD:Avec réservation pour évier:...) | In
893542 | 047
1579671 | 102
2008179 | 100

# IfcFurnishingElement: Casiers 1x2 (74)
Type - ElementType: Casiers 1x2; Material: Peinture - Grise, Peinture - Blanc
Name (Casiers 1x2:Casiers 1x2:...) | In
922434 | 078
922435 | 078
922436 | 078
922437 | 078
922607 | 078
922608 | 078
922965 | 110
922966 | 110
922967 | 110
922968 | 110
922969 | 110
923068 | 103
923258 | 043
923259 | 043
923260 | 043
1402291 | 110
1402292 | 110
1402293 | 110
1402294 | 110
1402295 | 110
1402654 | 078
1402655 | 078
1402656 | 078
1402657 | 078
1402658 | 078
1402799 | 079
1402800 | 079
1402801 | 079
1402802 | 079
1402803 | 079
1402804 | 079
1402805 | 079
1402806 | 079
1402807 | 079
1402808 | 079
1402809 | 079
1402862 | 080
1402863 | 080
1402864 | 080
1402865 | 080
1402866 | 080
1402867 | 080
1402868 | 080
1402869 | 080
1402870 | 080
1402871 | 080
1402872 | 080
1402873 | 081
1402874 | 081
1402875 | 081
1402876 | 081
1402877 | 081
1402878 | 081
1402879 | 081
1402880 | 081
1402881 | 081
1402882 | 081
1402883 | 081
1402914 | 081
1402915 | 081
1402916 | 081
1402917 | 080
1402918 | 080
1402919 | 080
1402920 | 078
1402921 | 078
1402922 | 079
1402923 | 079
1402924 | 079
1502105 | 103
1502113 | 103
1602682 | 043
1602683 | 043
1694105 | 078

# IfcFurnishingElement: Fauteuil (4)
In: 106
Type - ElementType: Fauteuil; Material: Plastique - Gris foncé, Cuir - Jaune
Name (Fauteuil:Fauteuil:...)
864727
864908
865079
865334

# IfcFurnishingElement: P-600 mm (4)
Type - ElementType: P-600 mm; Material: Bois - Mélaminé bleu
Name | In
Plan de travail - Emplacement rond pour lavabo-2:P-600 mm:858960 | 084
Plan de travail - Emplacement rond pour lavabo-4:P-600 mm:861772 | 103
Plan de travail - Emplacement rond pour lavabo:P-600 mm:1498118 | 043
Plan de travail - Emplacement rond pour lavabo-1:P-600 mm:1575728 | 082

# IfcFurnishingElement: P-600 mm 2, Plan de travail - Emplacement rond pour lavabo1:P-600 mm 2:1575729
In: 084
Type - ElementType: P-600 mm 2; Material: Bois - Mélaminé bleu

# IfcFurnishingElement: Sans réservation pour évier (5)
Type - ElementType: Sans réservation pour évier; Material: Bois - Mélaminé jaune pastel
Name (PTD:Sans réservation pour évier:...) | In
924407 | 025
929526 | 049
1007058 | 048
1092275 | RDC
1528687 | RDC

# IfcFurnishingElement: Siège - 03, Siège - 03:Siège - 03:927057
In: 026
Type - ElementType: Siège - 03; Material: Textile - Bleu, Plastique - Gris foncé

# IfcMember: Limon à la française:Limon à la française - 30 mm (73)
Type - PredefinedType: STRINGER
Material: Acier, 45-345
Pset_MemberCommon - LoadBearing: yes; IsExternal: no
Name (Escalier assemblé:Escalier:...) | In | Reference | Span (cm) | Slope (deg)
1434872 Stringer 1 | RDC | Escalier métallique | 3 | 0
1434872 Stringer 2 | RDC | Escalier métallique | 3 | 0
1434872 Stringer 3 | RDC | Escalier métallique | 3 | 0
1434872 Stringer 4 | RDC | Escalier métallique
1434872 Stringer 5 | RDC | Escalier métallique
1434872 Stringer 6 | RDC | Escalier métallique
1434872 Stringer 7 | RDC | Escalier métallique | 3 | 0
1434872 Stringer 8 | RDC | Escalier métallique | 3 | 0
1434872 Stringer 9 | RDC | Escalier métallique
1434872 Stringer 10 | RDC | Escalier métallique | 20 | 0
1434872 Stringer 11 | RDC | Escalier métallique
1434872 Stringer 12 | RDC | Escalier métallique | 20 | 0
1434872 Stringer 13 | RDC | Escalier métallique | 20 | 0
1444679 Stringer 1 | Acrotère E3 | Escalier métallique | 3 | 0
1444679 Stringer 2 | Acrotère E3 | Escalier métallique | 3 | 0
1444679 Stringer 3 | Acrotère E3 | Escalier métallique | 3 | 0
1444679 Stringer 4 | Acrotère E3 | Escalier métallique | 3 | 0
1444679 Stringer 5 | Acrotère E3 | Escalier métallique | 3 | 0
1444679 Stringer 6 | Acrotère E3 | Escalier métallique | 20 | 0
1444679 Stringer 7 | Acrotère E3 | Escalier métallique | 20 | 0
1444679 Stringer 8 | Acrotère E3 | Escalier métallique
1444679 Stringer 9 | Acrotère E3 | Escalier métallique | 3 | 0
1444679 Stringer 10 | Acrotère E3 | Escalier métallique | 20 | 0
1452997 Stringer 1 | Acrotère E3 | Escalier métallique toiture | 3 | 0
1452997 Stringer 2 | Acrotère E3 | Escalier métallique toiture | 3 | 0
1453682 Stringer 1 | Acrotère E3 | Escalier métallique | 3 | 0
1453682 Stringer 2 | Acrotère E3 | Escalier métallique | 3 | 0
1453682 Stringer 3 | Acrotère E3 | Escalier métallique | 3 | 0
1453682 Stringer 4 | Acrotère E3 | Escalier métallique | 3 | 0
1453682 Stringer 5 | Acrotère E3 | Escalier métallique | 3 | 0
1453682 Stringer 6 | Acrotère E3 | Escalier métallique | 20 | 0
1453682 Stringer 7 | Acrotère E3 | Escalier métallique | 20 | 0
1453682 Stringer 8 | Acrotère E3 | Escalier métallique
1453682 Stringer 9 | Acrotère E3 | Escalier métallique | 20 | 0
1453682 Stringer 10 | Acrotère E3 | Escalier métallique | 3 | 0
1453709 Stringer 1 | Acrotère E3 | Escalier métallique toiture | 3 | 0
1453709 Stringer 2 | Acrotère E3 | Escalier métallique toiture | 3 | 0
1453820 Stringer 1 | Acrotère E3 | Escalier métallique | 3 | 0
1453820 Stringer 2 | Acrotère E3 | Escalier métallique | 3 | 0
1453820 Stringer 3 | Acrotère E3 | Escalier métallique | 20 | 0
1453820 Stringer 4 | Acrotère E3 | Escalier métallique | 20 | 0
1453820 Stringer 5 | Acrotère E3 | Escalier métallique | 20 | 0
1453820 Stringer 6 | Acrotère E3 | Escalier métallique | 20 | 0
1453820 Stringer 7 | Acrotère E3 | Escalier métallique | 20 | 0
1453820 Stringer 8 | Acrotère E3 | Escalier métallique | 20 | 0
1453820 Stringer 9 | Acrotère E3 | Escalier métallique
1453820 Stringer 10 | Acrotère E3 | Escalier métallique | 20 | 0
1453845 Stringer 1 | Acrotère E3 | Escalier métallique toiture | 3 | 0
1453845 Stringer 2 | Acrotère E3 | Escalier métallique toiture | 3 | 0
1455266 Stringer 1 | 724 | Escalier métallique toiture | 3 | 0
1455266 Stringer 2 | 724 | Escalier métallique toiture | 3 | 0
1460621 Stringer 1 | Acrotère E3 | Escalier métallique toiture | 3 | 0
1460621 Stringer 2 | Acrotère E3 | Escalier métallique toiture | 3 | 0
1460621 Stringer 3 | Acrotère E3 | Escalier métallique toiture
1460621 Stringer 4 | Acrotère E3 | Escalier métallique toiture | 20 | 0
1460621 Stringer 5 | Acrotère E3 | Escalier métallique toiture
1461006 Stringer 1 | Acrotère E3 | Escalier métallique toiture | 3 | 0
1461006 Stringer 2 | Acrotère E3 | Escalier métallique toiture | 3 | 0
1461006 Stringer 3 | Acrotère E3 | Escalier métallique toiture
1461006 Stringer 4 | Acrotère E3 | Escalier métallique toiture
1461006 Stringer 5 | Acrotère E3 | Escalier métallique toiture | 20 | 0
1461847 Stringer 1 | Acrotère E3 | Escalier métallique toiture | 3 | 0
1461847 Stringer 2 | Acrotère E3 | Escalier métallique toiture | 3 | 0
1461847 Stringer 3 | Acrotère E3 | Escalier métallique toiture | 20 | 0
1461847 Stringer 4 | Acrotère E3 | Escalier métallique toiture | 20 | 0
1461847 Stringer 5 | Acrotère E3 | Escalier métallique toiture | 20 | 0
1461847 Stringer 6 | Acrotère E3 | Escalier métallique toiture | 20 | 0
1461963 Stringer 1 | Acrotère E3 | Escalier métallique toiture | 3 | 0
1461963 Stringer 2 | Acrotère E3 | Escalier métallique toiture | 3 | 0
1461963 Stringer 3 | Acrotère E3 | Escalier métallique toiture | 20 | 0
1461963 Stringer 4 | Acrotère E3 | Escalier métallique toiture | 20 | 0
1461963 Stringer 5 | Acrotère E3 | Escalier métallique toiture | 20 | 0
1461963 Stringer 6 | Acrotère E3 | Escalier métallique toiture | 20 | 0

# IfcMember: Mur-rideau:1 m x 1 m - Meneaux:661 (59)
In: R+1
Material: Plastique, blanc opaque
Pset_MemberCommon - LoadBearing: yes; IsExternal: no; Reference: 150 x 25mm
Name (Mur-rideau:1 m x 1 m - Meneaux:...) | Span (cm)
3 x 661 | 65.8974
661 | 89.2952
8 x 661 | 167
661 | 89
18 x 661 | 88.4012
4 x 661 | 93.5384
661 | 93.3494
661 | 73.1682
661 | 93.5644
661 | 91.7485
8 x 661 | 94
9 x 661 | 54
2 x 661 | 86.7485
661 | 172

# IfcMember: Mur-rideau:Simple panneau:1839252 (4)
In: RDC
Material: Plastique, blanc opaque
Pset_MemberCommon - LoadBearing: yes; IsExternal: no; Reference: 100 x 25mm ex; Span: 170 cm

# IfcMember: Mur-rideau:Simple panneau:1839338 (201)
Material: Plastique, blanc opaque
Pset_MemberCommon - LoadBearing: yes; IsExternal: no; Reference: 100 x 25mm 2
Name (Mur-rideau:Simple panneau:...) | In | Span (cm) | Group
2 x 1839338 | RDC | 280 | Groupe de modèles:mur-rideau-1:696009
1839338 | RDC | 168 | Groupe de modèles:mur-rideau-1:696009
24 x 1839338 | RDC | 160 | Groupe de modèles:fc-est-men-01:714451
41 x 1839338 | RDC | 100 | Groupe de modèles:fc-est-men-01:714451
2 x 1839338 | RDC | 59.5 | Groupe de modèles:fc-est-men-01:714451
1839338 | RDC | 94.4092 | Groupe de modèles:fc-est-men-01:714451
1839338 | RDC | 93 | Groupe de modèles:fc-est-men-01:714451
1839338 | RDC | 2.5 | Groupe de modèles:fc-est-men-01:714451
1839338 | RDC | 153.5 | Groupe de modèles:fc-est-men-01:714451
1839338 | RDC | 62 | Groupe de modèles:fc-est-men-01:714451
1839338 | RDC | 156 | Groupe de modèles:fc-est-men-01:714451
12 x 1839338 | RDC | 165
7 x 1839338 | RDC | 100
2 x 1839338 | RDC | 99.5
1839338 | R+1 | 160 | Groupe de modèles:fc-est-men-04:733328
2 x 1839338 | R+1 | 100 | Groupe de modèles:fc-est-men-04:733328
1839338 | R+1 | 160 | Groupe de modèles:fc-est-men-04:733672
2 x 1839338 | R+1 | 100 | Groupe de modèles:fc-est-men-04:733672
10 x 1839338 | RDC | 170
2 x 1839338 | RDC | 360
2 x 1839338 | R+1 | 208.5 | Groupe de modèles:men-2nd-j-100-hsup:836057
2 x 1839338 | R+1 | 90 | Groupe de modèles:men-2nd-j-100-hsup:836057
2 x 1839338 | R+1 | 208.5 | Groupe de modèles:men-2nd-j-100-hsup:836078
2 x 1839338 | R+1 | 90 | Groupe de modèles:men-2nd-j-100-hsup:836078
2 x 1839338 | R+1 | 208.5 | Groupe de modèles:men-2nd-j-100-hsup:836099
2 x 1839338 | R+1 | 90 | Groupe de modèles:men-2nd-j-100-hsup:836099
2 x 1839338 | R+1 | 208.5 | Groupe de modèles:men-2nd-j-100-hsup:836134
2 x 1839338 | R+1 | 90 | Groupe de modèles:men-2nd-j-100-hsup:836134
2 x 1839338 | R+1 | 208.5 | Groupe de modèles:men-2nd-j-100-hsup:836155
2 x 1839338 | R+1 | 90 | Groupe de modèles:men-2nd-j-100-hsup:836155
4 x 1839338 | R+1 | 389.25 | Groupe de modèles:shed2:1363791
8 x 1839338 | R+1 | 194.625 | Groupe de modèles:shed2:1363791
2 x 1839338 | R+1 | 177.084 | Groupe de modèles:shed1-:1363832
2 x 1839338 | R+1 | 1567 | Groupe de modèles:shed1-:1363832
2 x 1839338 | R+1 | 208.5 | Groupe de modèles:men-2nd-j-100-hsup:1449846
2 x 1839338 | R+1 | 90 | Groupe de modèles:men-2nd-j-100-hsup:1449846
6 x 1839338 | RDC | 160
1839338 | RDC | 101
1839338 | RDC | 103.5
3 x 1839338 | RDC | 102
8 x 1839338 | RDC | 90
2 x 1839338 | RDC | 204
2 x 1839338 | RDC | 350
2 x 1839338 | RDC | 500
1839338 | RDC | 473
2 x 1839338 | R+1 | 208.5 | Groupe de modèles:men-2nd-j-100-hsup:1628725
2 x 1839338 | R+1 | 90 | Groupe de modèles:men-2nd-j-100-hsup:1628725
2 x 1839338 | R+1 | 208.5 | Groupe de modèles:men-2nd-j-100-hsup:1628718
2 x 1839338 | R+1 | 90 | Groupe de modèles:men-2nd-j-100-hsup:1628718
2 x 1839338 | R+1 | 278 | Groupe de modèles:men-2nd-j-100-hsup 3:1631753
1839338 | R+1 | 90 | Groupe de modèles:men-2nd-j-100-hsup 3:1631753
5 x 1839338 | R+1 | 160
4 x 1839338 | R+1 | 100

# IfcMember: Mur-rideau:Simple panneau:450252 (367)
Material: Plastique, blanc opaque
Pset_MemberCommon - LoadBearing: yes; IsExternal: no; Reference: 100 x 25mm
Name (Mur-rideau:Simple panneau:...) | In | Span (cm)
450252 | RDC | 168 | Group: Groupe de modèles:mur-rideau-1:696009
3 x 450252 | RDC | 200 | Group: Groupe de modèles:fc-ouest-men-03:712083
2 x 450252 | RDC | 290 | Group: Groupe de modèles:fc-ouest-men-03:712083
2 x 450252 | RDC | 210 | Group: Groupe de modèles:fc-ouest-men-03:712083
4 x 450252 | RDC | 490 | Group: Groupe de modèles:porte-pliante-16mX5m:710013
4 x 450252 | RDC | 20 | Group: Groupe de modèles:porte-pliante-16mX5m:710013
24 x 450252 | RDC | 130 | Group: Groupe de modèles:porte-pliante-16mX5m:710013
2 x 450252 | RDC | 210 | Group: Groupe de modèles:fc-ouest-men-05:712792
2 x 450252 | RDC | 280 | Group: Groupe de modèles:fc-ouest-men-05:712792
4 x 450252 | RDC | 160 | Group: Groupe de modèles:fc-ouest-men-01:712563
2 x 450252 | RDC | 210 | Group: Groupe de modèles:fc-ouest-men-01:712563
2 x 450252 | RDC | 170 | Group: Groupe de modèles:fc-ouest-men-01:712563
2 x 450252 | RDC | 290 | Group: Groupe de modèles:fc-ouest-men-01:712563
450252 | RDC | 94.4092 | Group: Groupe de modèles:fc-est-men-01:714451
450252 | RDC | 100 | Group: Groupe de modèles:fc-est-men-01:714451
450252 | RDC | 100.5
3 x 450252 | RDC | 100
8 x 450252 | R+1 | 100 | Group: Groupe de modèles:fc-est-men-04:733328
5 x 450252 | R+1 | 160 | Group: Groupe de modèles:fc-est-men-04:733328
8 x 450252 | R+1 | 100 | Group: Groupe de modèles:fc-est-men-04:733672
5 x 450252 | R+1 | 160 | Group: Groupe de modèles:fc-est-men-04:733672
2 x 450252 | R+1 | 170 | Group: Groupe de modèles:fc-est-men-05:734619
2 x 450252 | R+1 | 145 | Group: Groupe de modèles:fc-est-men-05:734619
2 x 450252 | R+1 | 170 | Group: Groupe de modèles:fc-est-men-06:735172
2 x 450252 | R+1 | 350 | Group: Groupe de modèles:fc-est-men-06:735172
2 x 450252 | R+1 | 170 | Group: Groupe de modèles:fc-est-men-07:735197
2 x 450252 | R+1 | 412.2 | Group: Groupe de modèles:fc-est-men-07:735197
2 x 450252 | RDC | 170 | Group: Groupe de modèles:men-2nd-j-type3:750290
2 x 450252 | RDC | 205 | Group: Groupe de modèles:men-2nd-j-type3:750290
2 x 450252 | RDC | 170 | Group: Groupe de modèles:men-2nd-j-100:750974
2 x 450252 | RDC | 90 | Group: Groupe de modèles:men-2nd-j-100:750974
2 x 450252 | RDC | 170 | Group: Groupe de modèles:men-2nd-j-100:758245
2 x 450252 | RDC | 90 | Group: Groupe de modèles:men-2nd-j-100:758245
2 x 450252 | RDC | 72 | Group: Groupe de modèles:imposte-vitree-151cm:758786
2 x 450252 | RDC | 141 | Group: Groupe de modèles:imposte-vitree-151cm:758786
2 x 450252 | RDC | 72 | Group: Groupe de modèles:imposte-vitree-151cm:759193
2 x 450252 | RDC | 141 | Group: Groupe de modèles:imposte-vitree-151cm:759193
2 x 450252 | RDC | 170 | Group: Groupe de modèles:men-2nd-j-type3:759776
2 x 450252 | RDC | 205 | Group: Groupe de modèles:men-2nd-j-type3:759776
2 x 450252 | RDC | 170 | Group: Groupe de modèles:men-2nd-j-type3:759822
2 x 450252 | RDC | 205 | Group: Groupe de modèles:men-2nd-j-type3:759822
2 x 450252 | RDC | 170 | Group: Groupe de modèles:men-2nd-j-type5:760064
2 x 450252 | RDC | 410 | Group: Groupe de modèles:men-2nd-j-type5:760064
2 x 450252 | R+1 | 69.5 | Group: Groupe de modèles:imposte-vitree-102cm:836300
2 x 450252 | R+1 | 81.9506 | Group: Groupe de modèles:imposte-vitree-102cm:836300
2 x 450252 | R+1 | 69.5 | Group: Groupe de modèles:imposte-vitree-102cm:891748
2 x 450252 | R+1 | 92 | Group: Groupe de modèles:imposte-vitree-102cm:891748
2 x 450252 | RDC | 72 | Group: Groupe de modèles:imposte-vitree-204:968508
2 x 450252 | RDC | 92 | Group: Groupe de modèles:imposte-vitree-204:968508
2 x 450252 | RDC | 72 | Group: Groupe de modèles:imposte-vitree-102cm--:1247272
2 x 450252 | RDC | 92 | Group: Groupe de modèles:imposte-vitree-102cm--:1247272
2 x 450252 | RDC | 210 | Group: Groupe de modèles:fc-ouest-men-04:1282593
2 x 450252 | RDC | 170 | Group: Groupe de modèles:fc-ouest-men-04:1282593
2 x 450252 | RDC | 210 | Group: Groupe de modèles:fc-ouest-men-02:1284021
2 x 450252 | RDC | 170 | Group: Groupe de modèles:fc-ouest-men-02:1284021
4 x 450252 | RDC | 160 | Group: Groupe de modèles:fc-ouest-men-06:1222254
2 x 450252 | RDC | 140.103 | Group: Groupe de modèles:fc-ouest-men-06:1222254
2 x 450252 | RDC | 289.897 | Group: Groupe de modèles:fc-ouest-men-06:1222254
2 x 450252 | RDC | 290 | Group: Groupe de modèles:fc-ouest-men-06:1222254
2 x 450252 | RDC | 319.252
5 x 450252 | RDC | 415
2 x 450252 | RDC | 329.281
2 x 450252 | RDC | 389.217
2 x 450252 | RDC | 389.25
7 x 450252 | R+1 | 243 | Group: Groupe de modèles:shed2:1363791
7 x 450252 | R+1 | 316.984
2 x 450252 | R+1 | 334.281
2 x 450252 | R+1 | 319.252
4 x 450252 | R+1 | 194.608
4 x 450252 | R+1 | 194.625
2 x 450252 | RDC | 210 | Group: Groupe de modèles:fc-ouest-men-04:1406048
2 x 450252 | RDC | 170 | Group: Groupe de modèles:fc-ouest-men-04:1406048
2 x 450252 | RDC | 170 | Group: Groupe de modèles:men-2nd-j-100:1526733
2 x 450252 | RDC | 90 | Group: Groupe de modèles:men-2nd-j-100:1526733
6 x 450252 | RDC | 45
24 x 450252 | RDC | 95
17 x 450252 | RDC | 90
450252 | RDC | 89
450252 | RDC | 286
4 x 450252 | R+1 | 69.5
2 x 450252 | R+1 | 81.9506
450252 | R+1 | 90 | Group: Groupe de modèles:men-2nd-j-100-hsup 3:1631753
2 x 450252 | R+1 | 92
2 x 450252 | RDC | 72 | Group: Groupe de modèles:imposte-vitree-191 2:1657079
2 x 450252 | RDC | 181 | Group: Groupe de modèles:imposte-vitree-191 2:1657079
31 x 450252 | R+1 | 160
56 x 450252 | R+1 | 100
450252 | RDC | 145
450252 | RDC | 73
450252 | RDC | 144
2 x 450252 | RDC | 71.5
2 x 450252 | RDC | 194.5

# IfcMember: Mur-rideau:Simple panneau:661 (134)
In: RDC
Material: Plastique, blanc opaque
Pset_MemberCommon - LoadBearing: yes; IsExternal: no; Reference: 150 x 25mm
Name (Mur-rideau:Simple panneau:...) | Span (cm)
3 x 661 | 62
21 x 661 | 90
2 x 661 | 99.5
2 x 661 | 101
2 x 661 | 103.5
6 x 661 | 45
24 x 661 | 25
32 x 661 | 40
4 x 661 | 37.5
34 x 661 | 85
2 x 661 | 73
2 x 661 | 161

# IfcPlate: Plein (66)
Type - ElementType: Plein; PredefinedType: CURTAIN_PANEL; Material: Par défaut
Pset_PlateCommon - LoadBearing: yes; IsExternal: no; Reference: Plein; ThermalTransmittance: 3.7021 kg/K/s3
Name (Panneau système:Plein:...) | In
709953 | RDC | Group: Groupe de modèles:porte-pliante-16mX5m:710013
711006 | RDC | Group: Groupe de modèles:porte-pliante-16mX5m:710013
714971 | RDC | Group: Groupe de modèles:fc-est-men-01:714451
715042 | RDC | Group: Groupe de modèles:fc-est-men-01:714451
715528 | RDC | Group: Groupe de modèles:fc-est-men-01:714451
715833 | RDC | Group: Groupe de modèles:fc-est-men-01:714451
731476 | RDC | Group: Groupe de modèles:fc-est-men-01:714451
741787 | RDC
719130 | RDC
782354 | R+1
782355 | R+1
782356 | R+1
782357 | R+1
782358 | R+1
782359 | R+1
782360 | R+1
782361 | R+1
1604823 | RDC
1607776 | RDC
1607808 | RDC
1607812 | RDC
1607846 | RDC
1607858 | RDC
1607864 | RDC
1607870 | RDC
1607882 | RDC
1607900 | RDC
1607906 | RDC
1607930 | RDC
1607820 | RDC
1607824 | RDC
1607825 | RDC
1607847 | RDC
1607859 | RDC
1607865 | RDC
1607871 | RDC
1607883 | RDC
1607901 | RDC
1607907 | RDC
1607931 | RDC
1607830 | RDC
1607831 | RDC
1607832 | RDC
1607833 | RDC
1607834 | RDC
1607835 | RDC
1607836 | RDC
1607842 | RDC
1607848 | RDC
1607854 | RDC
1607860 | RDC
1607866 | RDC
1607872 | RDC
1607878 | RDC
1607884 | RDC
1607890 | RDC
1607896 | RDC
1607902 | RDC
1607908 | RDC
1607914 | RDC
1607920 | RDC
1607926 | RDC
1607932 | RDC
1627354 | RDC
1627358 | RDC
1627362 | RDC

# IfcPlate: Vitré (164)
Type - ElementType: Vitré; PredefinedType: CURTAIN_PANEL; Material: Verre
Pset_PlateCommon - LoadBearing: yes; IsExternal: no; Reference: Vitré; ThermalTransmittance: 6.7069 kg/K/s3
Name (Panneau système:Vitré:...) | In
693777 | RDC | Group: Groupe de modèles:mur-rideau-1:696009
703711 | RDC | Group: Groupe de modèles:fc-ouest-men-03:712083
1222138 | RDC | Group: Groupe de modèles:fc-ouest-men-03:712083
710924 | RDC | Group: Groupe de modèles:porte-pliante-16mX5m:710013
710063 | RDC | Group: Groupe de modèles:porte-pliante-16mX5m:710013
710120 | RDC | Group: Groupe de modèles:porte-pliante-16mX5m:710013
710176 | RDC | Group: Groupe de modèles:porte-pliante-16mX5m:710013
710222 | RDC | Group: Groupe de modèles:porte-pliante-16mX5m:710013
710282 | RDC | Group: Groupe de modèles:porte-pliante-16mX5m:710013
710318 | RDC | Group: Groupe de modèles:porte-pliante-16mX5m:710013
710360 | RDC | Group: Groupe de modèles:porte-pliante-16mX5m:710013
710470 | RDC | Group: Groupe de modèles:porte-pliante-16mX5m:710013
710530 | RDC | Group: Groupe de modèles:porte-pliante-16mX5m:710013
710632 | RDC | Group: Groupe de modèles:porte-pliante-16mX5m:710013
710690 | RDC | Group: Groupe de modèles:porte-pliante-16mX5m:710013
712246 | RDC | Group: Groupe de modèles:fc-ouest-men-05:712792
712562 | RDC | Group: Groupe de modèles:fc-ouest-men-01:712563
1221381 | RDC | Group: Groupe de modèles:fc-ouest-men-01:712563
1221463 | RDC | Group: Groupe de modèles:fc-ouest-men-01:712563
714305 | RDC | Group: Groupe de modèles:fc-est-men-01:714451
714910 | RDC | Group: Groupe de modèles:fc-est-men-01:714451
715101 | RDC | Group: Groupe de modèles:fc-est-men-01:714451
715219 | RDC | Group: Groupe de modèles:fc-est-men-01:714451
715353 | RDC | Group: Groupe de modèles:fc-est-men-01:714451
715479 | RDC | Group: Groupe de modèles:fc-est-men-01:714451
715575 | RDC | Group: Groupe de modèles:fc-est-men-01:714451
715792 | RDC | Group: Groupe de modèles:fc-est-men-01:714451
715896 | RDC | Group: Groupe de modèles:fc-est-men-01:714451
716093 | RDC | Group: Groupe de modèles:fc-est-men-01:714451
732412 | RDC | Group: Groupe de modèles:fc-est-men-01:714451
717007 | RDC
718917 | RDC
719076 | RDC
719204 | RDC
719356 | RDC
741659 | RDC
733056 | R+1 | Group: Groupe de modèles:fc-est-men-04:733328
733443 | R+1 | Group: Groupe de modèles:fc-est-men-04:733328
733372 | R+1 | Group: Groupe de modèles:fc-est-men-04:733328
733671 | R+1 | Group: Groupe de modèles:fc-est-men-04:733672
733678 | R+1 | Group: Groupe de modèles:fc-est-men-04:733672
733674 | R+1 | Group: Groupe de modèles:fc-est-men-04:733672
734569 | R+1 | Group: Groupe de modèles:fc-est-men-05:734619
734799 | R+1 | Group: Groupe de modèles:fc-est-men-06:735172
734949 | R+1 | Group: Groupe de modèles:fc-est-men-07:735197
748060 | RDC
750285 | RDC | Group: Groupe de modèles:men-2nd-j-type3:750290
750904 | RDC | Group: Groupe de modèles:men-2nd-j-100:750974
758244 | RDC | Group: Groupe de modèles:men-2nd-j-100:758245
758616 | RDC | Group: Groupe de modèles:imposte-vitree-151cm:758786
759192 | RDC | Group: Groupe de modèles:imposte-vitree-151cm:759193
759771 | RDC | Group: Groupe de modèles:men-2nd-j-type3:759776
759817 | RDC | Group: Groupe de modèles:men-2nd-j-type3:759822
760033 | RDC | Group: Groupe de modèles:men-2nd-j-type5:760064
782311 | R+1
782349 | R+1
782317 | R+1
782319 | R+1
782321 | R+1
782323 | R+1
782325 | R+1
782327 | R+1
782380 | R+1
782381 | R+1
782382 | R+1
782383 | R+1
782384 | R+1
782385 | R+1
782386 | R+1
782387 | R+1
836056 | R+1 | Group: Groupe de modèles:men-2nd-j-100-hsup:836057
836077 | R+1 | Group: Groupe de modèles:men-2nd-j-100-hsup:836078
836098 | R+1 | Group: Groupe de modèles:men-2nd-j-100-hsup:836099
836133 | R+1 | Group: Groupe de modèles:men-2nd-j-100-hsup:836134
836154 | R+1 | Group: Groupe de modèles:men-2nd-j-100-hsup:836155
836295 | R+1 | Group: Groupe de modèles:imposte-vitree-102cm:836300
891743 | R+1 | Group: Groupe de modèles:imposte-vitree-102cm:891748
968481 | RDC | Group: Groupe de modèles:imposte-vitree-204:968508
1119324 | RDC
1247237 | RDC | Group: Groupe de modèles:imposte-vitree-102cm--:1247272
1282592 | RDC | Group: Groupe de modèles:fc-ouest-men-04:1282593
1284020 | RDC | Group: Groupe de modèles:fc-ouest-men-02:1284021
1284646 | RDC | Group: Groupe de modèles:fc-ouest-men-06:1222254
1284652 | RDC | Group: Groupe de modèles:fc-ouest-men-06:1222254
1284656 | RDC | Group: Groupe de modèles:fc-ouest-men-06:1222254
1292163 | RDC
1292770 | RDC
1292845 | RDC
1292911 | RDC
1360495 | R+1 | Group: Groupe de modèles:shed2:1363791
2076181 | R+1 | Group: Groupe de modèles:shed2:1363791
1362083 | R+1 | Group: Groupe de modèles:shed1-:1363832
1362165 | R+1
1363126 | R+1
2002596 | R+1
1363026 | R+1
1406047 | RDC | Group: Groupe de modèles:fc-ouest-men-04:1406048
1449845 | R+1 | Group: Groupe de modèles:men-2nd-j-100-hsup:1449846
1526732 | RDC | Group: Groupe de modèles:men-2nd-j-100:1526733
1604211 | RDC
1604350 | RDC
1604369 | RDC
1604378 | RDC
1604396 | RDC
1604416 | RDC
1604435 | RDC
1604444 | RDC
1604462 | RDC
1607796 | RDC
1607800 | RDC
1607804 | RDC
1607816 | RDC
1607840 | RDC
1607852 | RDC
1607876 | RDC
1607888 | RDC
1607894 | RDC
1607912 | RDC
1607918 | RDC
1607924 | RDC
1607821 | RDC
1607822 | RDC
1607823 | RDC
1607826 | RDC
1607841 | RDC
1607853 | RDC
1607877 | RDC
1607889 | RDC
1607895 | RDC
1607913 | RDC
1607919 | RDC
1607925 | RDC
1608068 | RDC
1608087 | RDC
1608098 | RDC
1608116 | RDC
1608136 | RDC
1629919 | R+1 | Group: Groupe de modèles:men-2nd-j-100-hsup:1628725
1629928 | R+1 | Group: Groupe de modèles:men-2nd-j-100-hsup:1628718
1631722 | R+1
1631752 | R+1 | Group: Groupe de modèles:men-2nd-j-100-hsup 3:1631753
1631759 | R+1
1657074 | RDC | Group: Groupe de modèles:imposte-vitree-191 2:1657079
1744593 | R+1
1744599 | R+1
1744595 | R+1
1744619 | R+1
1744625 | R+1
1744621 | R+1
1744645 | R+1
1744651 | R+1
1744647 | R+1
1745366 | R+1
1745372 | R+1
1745368 | R+1
1745392 | R+1
1745398 | R+1
1745394 | R+1
1745418 | R+1
1745424 | R+1
1745420 | R+1
1877802 | RDC
1878108 | RDC
1880842 | RDC

# IfcRailing: Garde-corps:Au Mur (3)
In: RDC
Material: Pin (1)
Pset_RailingCommon - IsExternal: no; Reference: Au Mur; Height: 90 cm
Name (Garde-corps:Au Mur:...)
445835
988312
988316

# IfcRailing: Garde-corps:Type Bateau (20)
Material: Peinture - Grise, Pin (1)
Pset_RailingCommon - IsExternal: no; Reference: Type Bateau; Height: 90 cm
Name (Garde-corps:Type Bateau:...) | In
445831 | RDC
1158647 | Acrotère E3
1159071 | Acrotère E3
1170340 | Acrotère E3
1170678 | Acrotère E3
1170932 | Acrotère E3
1521033 | Acrotère E3
1521376 | Acrotère E3
1521421 | Acrotère E3
1521425 | Acrotère E3
1521542 | 724
1521546 | 724
1521582 | Acrotère E3
1521624 | Acrotère E3
1521628 | Acrotère E3
1522395 | Acrotère E3
1522611 | Acrotère E3
1522813 | Acrotère E3
1523039 | Acrotère E3
1924767 | Acrotère E3

# IfcRailing: Garde-corps:Type Bateau 2, Garde-corps:Type Bateau 2:1436463
In: RDC
Material: Peinture - Grise, Pin (1)
Pset_RailingCommon - IsExternal: no; Reference: Type Bateau 2; Height: 107 cm

# IfcRailing: Garde-corps:Type Bateau 3 (3)
Material: Peinture - Grise, Pin (1)
Pset_RailingCommon - IsExternal: no; Reference: Type Bateau 3; Height: 20 cm
Name (Garde-corps:Type Bateau 3:...) | In
1520996 | Acrotère E3
1522432 | Acrotère E3
1959266 | R+1

# IfcRamp: Rampe d'accès:Rampe d'accès Béton - 150 mm - 6%:970093 (2)
In: -77
Name (Rampe d'accès:Rampe d'accès Béton - 150 mm - 6%:...)
970100 | Material: Maçonnerie - Béton
970100 | Pset_RampCommon - IsExternal: no; Reference: Rampe d'accès Béton - 150 mm - 6%

# IfcRoof: Toit de base:ET 2 + ISO 17 + BET 22 (3)
Pset_RoofCommon - IsExternal: yes; Reference: ET 2 + ISO 17 + BET 22
Name (Toit de base:ET 2 + ISO 17 + BET 22:...) | In | TotalArea (m2) | ProjectedArea (m2)
972953 | Acrotère E3 | 269.1 | 270.1
1159829 | R+1 | 128.704 | 128.704
1248660 | Acrotère E3 | 46.25 | 46.25

# IfcRoof: Toit de base:ET 2 +ISO 25 + BAC 5 (4)
In: Acrotère EXT2
Pset_RoofCommon - IsExternal: yes; Reference: ET 2 +ISO 25 + BAC 5
Name (Toit de base:ET 2 +ISO 25 + BAC 5:...) | TotalArea (m2) | ProjectedArea (m2)
1203141 | 199.807 | 199.685
1203425 | 59.9807 | 59.9441
1203542 | 81.4809 | 81.4313
1203636 | 17.3719 | 16.546

# IfcRoof: Toit de base:MET 5 + ISO 26 + BAC 5 (3)
In: Acrotère EXT2
Pset_RoofCommon - IsExternal: yes; Reference: MET 5 + ISO 26 + BAC 5
Name (Toit de base:MET 5 + ISO 26 + BAC 5:...) | TotalArea (m2) | ProjectedArea (m2)
901057 | 109.937 | 95.9368
951634 | 85.2179 | 74.7493
2082774 | 136.359 | 119.111

# IfcRoof: Toit de base:Toit - 50 mm, Toit de base:Toit - 50 mm:993186
In: R+1
Pset_RoofCommon - IsExternal: yes; Reference: Toit - 50 mm; TotalArea: 46.3536 m2; ProjectedArea: 46.3536 m2

# IfcRoof: Toit de base:Toit_Multicouche_20 cm (3)
Pset_RoofCommon - IsExternal: yes; Reference: Toit_Multicouche_20 cm
Name (Toit de base:Toit_Multicouche_20 cm:...) | In | TotalArea (m2) | ProjectedArea (m2)
963996 | Acrotère E2 | 174.76 | 174.653
964005 | Acrotère E3 | 392.866 | 400.982
964013 | Acrotère E3 | 271.069 | 274.901

# IfcSlab: Escalier assemblé:Escalier métallique toiture:1453153 (4)
In: Acrotère E3
PredefinedType: LANDING; Material: Acier, 45-345
Pset_SlabCommon - IsExternal: no; PitchAngle: 0 deg; Reference: Palier non-monobloc
Name (Escalier assemblé:Escalier:...)
1460621 Landing 1
1461006 Landing 1
1461847 Landing 1
1461963 Landing 1

# IfcSlab: Escalier assemblé:Escalier métallique:1432133 (7)
PredefinedType: LANDING; Material: Acier, 45-345
Pset_SlabCommon - IsExternal: no; PitchAngle: 0 deg; Reference: Palier non-monobloc
Name (Escalier assemblé:Escalier:...) | In
1434872 Landing 1 | RDC
1434872 Landing 2 | RDC
1444679 Landing 1 | Acrotère E3
1444679 Landing 2 | Acrotère E3
1453682 Landing 1 | Acrotère E3
1453682 Landing 2 | Acrotère E3
1453820 Landing 1 | Acrotère E3

# IfcSlab: Sol:Béton 160 mm avec platelage métallique 50 mm (6)
PredefinedType: FLOOR; Material: Maçonnerie - Béton 21 cm
Pset_SlabCommon - LoadBearing: yes; IsExternal: no; Reference: Béton 160 mm avec platelage métallique 50 mm; ThermalTransmittance: 1000000000000000019884624838656 kg/K/s3; PitchAngle: 0 deg
Name (Sol:Béton 160 mm avec platelage métallique 50 mm:...) | In
434572 | R+1
743647 | R+1
745854 | R+1
782286 | R+1
963970 | R+1
964030 | Toiture E2

# IfcSlab: Sol:Dalle en béton - 100 mm (4)
PredefinedType: FLOOR; Material: Maçonnerie - Béton 11 cm
Pset_SlabCommon - LoadBearing: no; IsExternal: no; PitchAngle: 0 deg; Reference: Dalle en béton - 100 mm
Name (Sol:Dalle en béton - 100 mm:...) | In
1466571 | R+1
1593496 | RDC
1775292 | R+1
1775551 | R+1

# IfcSlab: Sol:Dalle en béton - 230 mm (2)
In: R+1
PredefinedType: FLOOR; Material: Maçonnerie - Béton 23 cm
Pset_SlabCommon - LoadBearing: no; IsExternal: no; Reference: Dalle en béton - 230 mm
Name (Sol:Dalle en béton - 230 mm:...)
1419566
1419566:2

# IfcSlab: Sol:Dalle en béton - 250 mm (4)
In: RDC
PredefinedType: FLOOR; Material: Maçonnerie - Béton 25 cm
Pset_SlabCommon - LoadBearing: no; IsExternal: no; PitchAngle: 0 deg; Reference: Dalle en béton - 250 mm
Name (Sol:Dalle en béton - 250 mm:...)
1447876
1593449
1593456
1593462

# IfcSlab: Sol:Dalle en béton PROJET - 230 mm (2)
PredefinedType: FLOOR; Material: Béton, coulé sur place, gris 23 cm
Pset_SlabCommon - LoadBearing: no; IsExternal: no; PitchAngle: 0 deg; Reference: Dalle en béton PROJET - 230 mm; ThermalTransmittance: 4.54783 kg/K/s3
Name (Sol:Dalle en béton PROJET - 230 mm:...) | In
671408 | R+1
753161 | RDC

# IfcSlab: Sol:Dalle en béton PROJET - 250 mm, Sol:Dalle en béton PROJET - 250 mm:671024
In: RDC
PredefinedType: FLOOR; Material: Béton, coulé sur place, gris 25 cm
Pset_SlabCommon - LoadBearing: no; IsExternal: no; Reference: Dalle en béton PROJET - 250 mm; ThermalTransmittance: 4.184 kg/K/s3

# IfcSlab: Sol:Etancheite 4 (3)
In: R+1
PredefinedType: FLOOR; Material: Maçonnerie - Isolant_MU 4 cm
Pset_SlabCommon - LoadBearing: no; IsExternal: no; PitchAngle: 0 deg; Reference: Etancheite 4
Name (Sol:Etancheite 4:...)
1685445
1688327
1776389

# IfcSlab: Sol:Iso 20 (2)
In: RDC
PredefinedType: FLOOR; Material: Maçonnerie - Isolant_MU 20 cm
Pset_SlabCommon - LoadBearing: no; IsExternal: no; Reference: Iso 20
Name (Sol:Iso 20:...)
1837474
1859216

# IfcSlab: Toit de base:ET 2 + ISO 17 + BET 22 (3)
PredefinedType: ROOF; Material: Toiture, membrane EPDM 2 cm, Laine minérale 17 cm, Béton, coulé sur place, gris(1) 22 cm
Pset_SlabCommon - IsExternal: yes; PitchAngle: 0 deg; Reference: ET 2 + ISO 17 + BET 22; ThermalTransmittance: 0.186733 kg/K/s3
Name (Toit de base:ET 2 + ISO 17 + BET 22:...) | In
972953 | Acrotère E3
1159829 | R+1
1248660 | Acrotère E3

# IfcSlab: Toit de base:ET 2 +ISO 25 + BAC 5 (4)
In: Acrotère EXT2
PredefinedType: ROOF; Material: Toiture, membrane EPDM 2 cm, Laine minérale 25 cm, Acier 5 cm
Pset_SlabCommon - IsExternal: yes; Reference: ET 2 +ISO 25 + BAC 5; ThermalTransmittance: 0.133355 kg/K/s3; PitchAngle: 2 deg
Name (Toit de base:ET 2 +ISO 25 + BAC 5:...)
1203141
1203425
1203542
1203636

# IfcSlab: Toit de base:MET 5 + ISO 26 + BAC 5 (3)
In: Acrotère EXT2
PredefinedType: ROOF; Material: Tôle/Doublage(PROJET)BLEU 5 cm, Laine minérale 32 cm
Pset_SlabCommon - IsExternal: yes; Reference: MET 5 + ISO 26 + BAC 5; ThermalTransmittance: 0.106248 kg/K/s3
Name (Toit de base:MET 5 + ISO 26 + BAC 5:...) | PitchAngle (deg)
901057 | 29.2318
951634 | 28.699
2082774 | 29.131

# IfcSlab: Toit de base:Toit - 50 mm, Toit de base:Toit - 50 mm:993186
In: R+1
PredefinedType: ROOF; Material: Tôle/Doublage(PROJET) 5 cm
Pset_SlabCommon - IsExternal: yes; PitchAngle: 0 deg; Reference: Toit - 50 mm; ThermalTransmittance: 4600 kg/K/s3

# IfcSlab: Toit de base:Toit_Multicouche_20 cm (3)
PredefinedType: ROOF; Material: Toiture, membrane EPDM 2 cm, Laine minérale 10.5 cm, Acier 7.5 cm
Pset_SlabCommon - IsExternal: yes; Reference: Toit_Multicouche_20 cm; ThermalTransmittance: 0.309167 kg/K/s3; PitchAngle: 2 deg
Name (Toit de base:Toit_Multicouche_20 cm:...) | In
963996 | Acrotère E2
964005 | Acrotère E3
964013 | Acrotère E3

# IfcStair: Escalier assemblé:Escalier métallique toiture:1453153 (8)
Pset_StairCommon - IsExternal: no; Reference: Escalier métallique toiture
Name (Escalier assemblé:Escalier:...) | In | NumberOfRiser | NumberOfTreads | RiserHeight (cm) | TreadLength (cm)
1452997 | Acrotère E3 | 4 | 3 | 18.2222 | 29
1453709 | Acrotère E3 | 4 | 3 | 18.2222 | 29
1453845 | Acrotère E3 | 4 | 3 | 18.2222 | 29
1455266 | 724 | 5 | 4 | 18.7143 | 29
1460621 | Acrotère E3 | 7 | 6 | 18.7143 | 25
1461006 | Acrotère E3 | 5 | 4 | 18.7143 | 25
1461847 | Acrotère E3 | 5 | 4 | 18.7143 | 25
1461963 | Acrotère E3 | 4 | 3 | 18.2222 | 29

# IfcStair: Escalier assemblé:Escalier métallique:1432133 (4)
Pset_StairCommon - IsExternal: no; Reference: Escalier métallique; TreadLength: 29 cm
Name (Escalier assemblé:Escalier:...) | In | NumberOfRiser | NumberOfTreads | RiserHeight (cm)
1434872 | RDC | 22 | 19 | 15.5909
1444679 | Acrotère E3 | 9 | 7 | 14.5556
1453682 | Acrotère E3 | 9 | 7 | 14.5556
1453820 | Acrotère E3 | 3 | 2 | 14.5556

# IfcStair: Escalier coulé sur place:Monobloc:189391, Escalier coulé sur place:Escalier:445164
In: RDC
Pset_StairCommon - IsExternal: no; Reference: Monobloc; NumberOfRiser: 19; NumberOfTreads: 18; RiserHeight: 16.3333 cm; TreadLength: 30.3333 cm

# IfcStair: Escalier:Monobloc:28673 (2)
In: RDC
Name (Escalier:Monobloc:...)
672908 | Material: Maçonnerie - Béton
672908 | Pset_StairCommon - IsExternal: no; Reference: Monobloc; NumberOfRiser: 22; NumberOfTreads: 22; RiserHeight: 15.5909 cm; TreadLength: 28 cm

# IfcStairFlight: Escalier assemblé:Escalier métallique toiture:1453153 (8)
Material: Acier, 45-345
Pset_StairFlightCommon - NosingLength: 0 cm; Reference: Marche 30 mm; WalkingLineOffset: 45 cm; WaistThickness: 90 cm
Name (Escalier assemblé:Escalier:...) | In | NumberOfRiser = Pset_StairFlightCommon, NumberOfRiser | NumberOfTreads = Pset_StairFlightCommon, NumberOfTreads | RiserHeight (cm) | TreadLength (cm) | Pset_StairFlightCommon, RiserHeight (cm) | Pset_StairFlightCommon, TreadLength (cm) = TreadLengthAtOffset (cm)
1452997 Run 1 | Acrotère E3 | 4 | 3 | 0.597842 | 0.951444 | 18.2222 | 29
1453709 Run 1 | Acrotère E3 | 4 | 3 | 0.597842 | 0.951444 | 18.2222 | 29
1453845 Run 1 | Acrotère E3 | 4 | 3 | 0.597842 | 0.951444 | 18.2222 | 29
1455266 Run 1 | 724 | 5 | 4 | 0.613986 | 0.951444 | 18.7143 | 29
1460621 Run 1 | Acrotère E3 | 7 | 6 | 0.613986 | 0.82021 | 18.7143 | 25
1461006 Run 1 | Acrotère E3 | 5 | 4 | 0.613986 | 0.82021 | 18.7143 | 25
1461847 Run 1 | Acrotère E3 | 5 | 4 | 0.613986 | 0.82021 | 18.7143 | 25
1461963 Run 1 | Acrotère E3 | 4 | 3 | 0.597842 | 0.951444 | 18.2222 | 29

# IfcStairFlight: Escalier assemblé:Escalier métallique:1432133 (8)
TreadLength: 0.951444 cm; Material: Acier, 45-345
Pset_StairFlightCommon - NosingLength: 0 cm; Reference: Marche 30 mm; TreadLength: 29 cm; TreadLengthAtOffset: 29 cm
Name (Escalier assemblé:Escalier:...) | In | NumberOfRiser | NumberOfTreads | RiserHeight (cm) | Pset_StairFlightCommon, NumberOfRiser | Pset_StairFlightCommon, NumberOfTreads | Pset_StairFlightCommon, RiserHeight (cm) | WalkingLineOffset (cm) | WaistThickness (cm)
1434872 Run 1 | RDC | 6 | 5 | 0.511513 | 22 | 19 | 15.5909 | 81.5247 | 163.049
1434872 Run 2 | RDC | 8 | 7 | 0.511513 | 22 | 19 | 15.5909 | 75 | 150
1434872 Run 3 | RDC | 8 | 7 | 0.511513 | 22 | 19 | 15.5909 | 75 | 150
1444679 Run 1 | Acrotère E3 | 6 | 5 | 0.477544 | 9 | 7 | 14.5556 | 45 | 90
1444679 Run 2 | Acrotère E3 | 3 | 2 | 0.477544 | 9 | 7 | 14.5556 | 45 | 90
1453682 Run 1 | Acrotère E3 | 6 | 5 | 0.477544 | 9 | 7 | 14.5556 | 45 | 90
1453682 Run 2 | Acrotère E3 | 3 | 2 | 0.477544 | 9 | 7 | 14.5556 | 45 | 90
1453820 Run 1 | Acrotère E3 | 3 | 2 | 0.477544 | 3 | 2 | 14.5556 | 45 | 90

# IfcStairFlight: Escalier coulé sur place:Monobloc:189391, Escalier coulé sur place:Escalier:445164 Run 1
In: RDC
NumberOfRiser: 19; NumberOfTreads: 18; RiserHeight: 0.535871 cm; TreadLength: 0.995188 cm; Material: Maçonnerie - Béton
Pset_StairFlightCommon - Reference: Profondeur de structure 80 mm; NumberOfRiser: 19; NumberOfTreads: 18; RiserHeight: 16.3333 cm; TreadLength: 30.3333 cm; TreadLengthAtOffset: 30.3333 cm; NosingLength: 0 cm; WalkingLineOffset: 75 cm; WaistThickness: 150 cm

# IfcWall: Mur de base:ACOUST 7 + BET 20, Mur de base:ACOUST 7 + BET 20:643870
In: RDC
Material: Béton, coulé sur place, gris
Pset_WallCommon - LoadBearing: yes; ExtendToStructure: no; IsExternal: yes; Reference: ACOUST 7 + BET 20; ThermalTransmittance: 5.23 kg/K/s3

# IfcWall: Mur de base:BET 20 (5)
In: RDC
Type - PredefinedType: STANDARD; Material: Béton, coulé sur place, gris 20 cm
Pset_WallCommon - IsExternal: yes; Reference: BET 20; ThermalTransmittance: 5.23 kg/K/s3
Name (Mur de base:BET 20:...) | ExtendToStructure | LoadBearing
650642 | no | no
651030 | yes | yes
651375 | no | yes
682656 | yes | yes
1834084 | no | no

# IfcWall: Mur de base:BET 21, Mur de base:BET 21:644479
In: RDC
Material: Béton, coulé sur place, gris
Pset_WallCommon - LoadBearing: yes; ExtendToStructure: no; IsExternal: yes; Reference: BET 21; ThermalTransmittance: 5.23 kg/K/s3

# IfcWall: Mur de base:END 1 + PAR 20 + ISO 10 + PLA 1 (2)
In: RDC
Type - PredefinedType: STANDARD; Material: Maçonnerie - Enduit 1 cm, Maçonnerie 20 cm, Laine minérale 10 cm, Plâtre 1 cm
Pset_WallCommon - Reference: END 1 + PAR 20 + ISO 10 + PLA 1; LoadBearing: yes; ExtendToStructure: no; IsExternal: yes; ThermalTransmittance: 0.321065 kg/K/s3
Name (Mur de base:END 1 + PAR 20 + ISO 10 + PLA 1:...)
323806
1111719

# IfcWall: Mur de base:ISO 23 (3)
In: Acrotère EXT2
Material: Laine minérale
Pset_WallCommon - ExtendToStructure: no; IsExternal: yes; LoadBearing: no; Reference: ISO 23; ThermalTransmittance: 0.147826 kg/K/s3
Name (Mur de base:ISO 23:...)
1472664
1473377
1473846

# IfcWall: Mur de base:Int. plâtre 100 mm, Mur de base:Int. plâtre 100 mm:535420
In: R+1
Material: Plâtre
Pset_WallCommon - ExtendToStructure: no; LoadBearing: no; IsExternal: no; Reference: Int. plâtre 100 mm; ThermalTransmittance: 5.1 kg/K/s3

# IfcWall: Mur de base:MET 4 + ISO 14 + PLA 2, Mur de base:MET 4 + ISO 14 + PLA 2:1096427
In: RDC
Material: Tôle/Doublage, Laine minérale, Plâtre
Pset_WallCommon - ExtendToStructure: no; IsExternal: yes; LoadBearing: no; Reference: MET 4 + ISO 14 + PLA 2; ThermalTransmittance: 0.240556 kg/K/s3

# IfcWall: Mur de base:MET 4 + ISO 6 + MET 1, Mur de base:MET 4 + ISO 6 + MET 1:480621
In: RDC
Material: Tôle/Doublage (2), Laine minérale
Pset_WallCommon - ExtendToStructure: no; IsExternal: yes; LoadBearing: no; Reference: MET 4 + ISO 6 + MET 1; ThermalTransmittance: 0.566597 kg/K/s3

# IfcWall: Mur de base:MET 4 + ISO 6 + MET 2, Mur de base:MET 4 + ISO 6 + MET 2:406757
In: RDC
Material: Tôle/Doublage (2), Laine minérale
Pset_WallCommon - ExtendToStructure: no; IsExternal: yes; LoadBearing: no; Reference: MET 4 + ISO 6 + MET 2; ThermalTransmittance: 0.566597 kg/K/s3

# IfcWall: Mur de base:MET 4 + ISO 8 + PLA 2 (4)
In: R+1
Type - PredefinedType: STANDARD; Material: Tôle/Doublage 4 cm, Laine minérale 8 cm, Plâtre 2 cm
Pset_WallCommon - ExtendToStructure: no; IsExternal: yes; LoadBearing: no; Reference: MET 4 + ISO 8 + PLA 2; ThermalTransmittance: 0.418002 kg/K/s3
Name (Mur de base:MET 4 + ISO 8 + PLA 2:...)
488873
507177
509558
1102006

# IfcWall: Mur de base:MET PROJET 4 + ISO 23 (2)
In: RDC
Pset_WallCommon - LoadBearing: yes; ExtendToStructure: no; IsExternal: yes; Reference: MET PROJET 4 + ISO 23; ThermalTransmittance: 0.147822 kg/K/s3
Name (Mur de base:MET PROJET 4 + ISO 23:...)
1745170 | Material: Tôle/Doublage(PROJET), Laine minérale
1750900

# IfcWall: Mur de base:MET PROJET 4 + ISO 23 + MET 1 (2)
Pset_WallCommon - ExtendToStructure: no; IsExternal: yes; Reference: MET PROJET 4 + ISO 23 + MET 1; ThermalTransmittance: 0.15454 kg/K/s3
Name (Mur de base:MET PROJET 4 + ISO 23 + MET 1:...) | In | LoadBearing
656004 | RDC | no | Material: Tôle/Doublage(PROJET) (2), Laine minérale
1204164 | Acrotère E2 | yes

# IfcWall: Mur de base:MET PROJET 4 + ISO 23 + MET 2 bis, Mur de base:MET PROJET 4 + ISO 23 + MET 2 bis:1358550
In: Acrotère E2
Type - PredefinedType: STANDARD; Material: Tôle/Doublage(PROJET) 4 cm, Laine minérale 22 cm, Plateau-acier-perforé 1 cm
Pset_WallCommon - LoadBearing: yes; ExtendToStructure: no; IsExternal: yes; Reference: MET PROJET 4 + ISO 23 + MET 2 bis; ThermalTransmittance: 0.15454 kg/K/s3

# IfcWall: Mur de base:PLA 1.25 + ISO 9.5 + MET 4 (4)
In: RDC
Type - PredefinedType: STANDARD; Material: Tôle/Doublage 2 cm, Laine minérale 9.5 cm, Plâtre_MU 1.25 cm
Pset_WallCommon - ExtendToStructure: no; IsExternal: yes; LoadBearing: no; Reference: PLA 1.25 + ISO 9.5 + MET 4; ThermalTransmittance: 0.354772 kg/K/s3
Name (Mur de base:PLA 1.25 + ISO 9.5 + MET 4:...)
744107
744681
745099
745101

# IfcWall: Mur de base:PLA 10, Mur de base:PLA 10:661256
In: R+1
Type - PredefinedType: STANDARD; Material: Plâtre 10 cm
Pset_WallCommon - LoadBearing: yes; ExtendToStructure: no; IsExternal: no; ThermalTransmittance: 5.1 kg/K/s3; Reference: PLA 10

# IfcWall: Mur de base:PLA 2 + PAR 20, Mur de base:PLA 2 + PAR 20:534439
In: RDC
Type - PredefinedType: STANDARD; Material: Plâtre 2 cm, Maçonnerie 20 cm
Pset_WallCommon - IsExternal: yes; ExtendToStructure: yes; LoadBearing: no; Reference: PLA 2 + PAR 20; ThermalTransmittance: 5.17969 kg/K/s3

# IfcWallStandardCase: Mur de base:ACOUST 5 (7)
Type - PredefinedType: STANDARD; Material: Laine minérale 3 cm, Panneau de grandes particules orientées 2 cm
Pset_WallCommon - ExtendToStructure: no; IsExternal: yes; LoadBearing: no; Reference: ACOUST 5; ThermalTransmittance: 0.953271 kg/K/s3
Name (Mur de base:ACOUST 5:...) | In
1768838 | R+1
1768980 | R+1
1769417 | R+1
1769490 | R+1
1774708 | R+1
1774808 | R+1
1919857 | RDC

# IfcWallStandardCase: Mur de base:ACOUST 7 (2)
Type - PredefinedType: STANDARD; Material: Panneau de grandes particules orientées 3.5 cm
Pset_WallCommon - ExtendToStructure: no; IsExternal: yes; LoadBearing: no; Reference: ACOUST 7; ThermalTransmittance: 3.42857 kg/K/s3
Name (Mur de base:ACOUST 7:...) | In
1017082 | R+1
1759308 | RDC

# IfcWallStandardCase: Mur de base:ACOUST panneaux fibres (21)
Type - PredefinedType: STANDARD; Material: Laine minérale 3 cm, Panneau de grandes particules orientées(1) 2 cm
Pset_WallCommon - ExtendToStructure: no; IsExternal: yes; LoadBearing: no; Reference: ACOUST panneaux fibres; ThermalTransmittance: 0.953271 kg/K/s3
Name (Mur de base:ACOUST panneaux fibres:...) | In
1769298 | R+1
1769370 | R+1
1907894 | R+1
1918556 | RDC
1919233 | RDC
1919367 | RDC
1919440 | RDC
1919610 | RDC
1919780 | RDC
1920384 | RDC
1920492 | RDC
1920555 | RDC
1920601 | RDC
1920714 | RDC
1920764 | RDC
1920801 | RDC
1921608 | RDC
1921702 | RDC
1921789 | RDC
1921868 | RDC
2068001 | RDC

# IfcWallStandardCase: Mur de base:BET 20 (30)
Type - PredefinedType: STANDARD; Material: Béton, coulé sur place, gris 20 cm
Pset_WallCommon - IsExternal: yes; Reference: BET 20; ThermalTransmittance: 5.23 kg/K/s3
Name (Mur de base:BET 20:...) | In | LoadBearing | ExtendToStructure
645036 | RDC | yes | no
650060 | RDC | yes | no
650682 | RDC | no | no
650916 | RDC | no | yes
651654 | RDC | yes | no
652200 | RDC | yes | yes
660562 | R+1 | yes | no
661156 | R+1 | no | no
663909 | R+1 | yes | no
678807 | R+1 | yes | no
743473 | RDC | no | yes
838330 | R+1 | yes | no
1250581 | R+1 | yes | no
1258435 | R+1 | yes | no
1267540 | RDC | no | yes
1267628 | RDC | no | yes
1267740 | RDC | no | no
1329516 | RDC | no | yes
1337653 | RDC | no | yes
1836228 | RDC | no | no
1873194 | RDC | no | no
1874683 | RDC | no | no
1874689 | RDC | no | no
1874695 | RDC | no | no
1874701 | RDC | no | no
1874707 | RDC | no | no
1874713 | RDC | no | no
1874719 | RDC | no | no
1874725 | RDC | no | no
1874731 | RDC | no | no

# IfcWallStandardCase: Mur de base:BET 21 (3)
Material: Béton, coulé sur place, gris 20 cm
Pset_WallCommon - LoadBearing: yes; ExtendToStructure: no; IsExternal: yes; Reference: BET 21; ThermalTransmittance: 5.23 kg/K/s3
Name (Mur de base:BET 21:...) | In
644761 | RDC
656273 | RDC
679412 | R+1

# IfcWallStandardCase: Mur de base:CAR 2 (8)
In: RDC
Type - PredefinedType: STANDARD; Material: MU_carrelage_mural 2 cm
Pset_WallCommon - ExtendToStructure: no; LoadBearing: no; IsExternal: no; Reference: CAR 2; FireRating: CF 1/2 H
Name (Mur de base:CAR 2:...)
1806358
1813865
1814003
1814462
1814602
1814698
1814760
1814808

# IfcWallStandardCase: Mur de base:CIM 10 (13)
Type - PredefinedType: STANDARD; Material: Stuc 10 cm
Pset_WallCommon - LoadBearing: no; IsExternal: no; Reference: CIM 10; ThermalTransmittance: 7.2 kg/K/s3
Name (Mur de base:CIM 10:...) | In | ExtendToStructure
648159 | RDC | yes
648296 | RDC | yes
649732 | RDC | yes
649870 | RDC | yes
651466 | RDC | yes
652393 | RDC | yes
652493 | RDC | yes
652631 | RDC | yes
652761 | RDC | no
653759 | RDC | yes
653884 | RDC | yes
661309 | R+1 | no
1074167 | RDC | yes

# IfcWallStandardCase: Mur de base:END 1 + PAR 20 + ISO 10 + PLA 1 (15)
In: RDC
Type - PredefinedType: STANDARD; Material: Maçonnerie - Enduit 1 cm, Maçonnerie 20 cm, Laine minérale 10 cm, Plâtre 1 cm
Pset_WallCommon - Reference: END 1 + PAR 20 + ISO 10 + PLA 1; LoadBearing: yes; IsExternal: yes; ThermalTransmittance: 0.321065 kg/K/s3
Name (Mur de base:END 1 + PAR 20 + ISO 10 + PLA 1:...) | ExtendToStructure
323247 | no
323280 | no
323385 | yes
323541 | no
323750 | no
323906 | no
325008 | no
325566 | no
326025 | no
326480 | no
326715 | no
327490 | yes
359864 | no
1109763 | no
1111443 | no

# IfcWallStandardCase: Mur de base:ISO 10 + MET 2 (5)
In: RDC
Type - PredefinedType: STANDARD; Material: Plâtre_MU 1.25 cm, Laine minérale 9.5 cm, Plâtre_MU 1.25 cm
Pset_WallCommon - IsExternal: yes; LoadBearing: no; Reference: ISO 10 + MET 2; ThermalTransmittance: 0.351724 kg/K/s3
Name (Mur de base:ISO 10 + MET 2:...) | ExtendToStructure
744067 | yes
744682 | no
744848 | no
745102 | yes
745230 | no

# IfcWallStandardCase: Mur de base:ISO 10 + MET 3 -EX, Mur de base:ISO 10 + MET 3 -EX:1863523
In: Acrotère E2
Type - PredefinedType: STANDARD; Material: Laine minérale 9.5 cm, Platelage métallique 1.25 cm
Pset_WallCommon - ExtendToStructure: no; IsExternal: yes; LoadBearing: no; Reference: ISO 10 + MET 3 -EX; ThermalTransmittance: 0.357859 kg/K/s3

# IfcWallStandardCase: Mur de base:Int. PLA 10cm_MU (3)
In: RDC
Type - PredefinedType: STANDARD; Material: Mur par défaut 10 cm
Pset_WallCommon - ExtendToStructure: no; LoadBearing: no; IsExternal: no; Reference: Int. PLA 10cm_MU; FireRating: CF : Durée à définir
Pset_ManufacturerTypeInformation - Manufacturer: Mûrisserie Architecture
Name (Mur de base:Int. PLA 10cm_MU:...)
1794540
1794669
1794718

# IfcWallStandardCase: Mur de base:Int. plâtre 100 mm (3)
Material: Plâtre 10 cm
Pset_WallCommon - ExtendToStructure: no; LoadBearing: no; IsExternal: no; Reference: Int. plâtre 100 mm; ThermalTransmittance: 5.1 kg/K/s3
Name (Mur de base:Int. plâtre 100 mm:...) | In
535723 | R+1
1114477 | RDC
1114559 | RDC

# IfcWallStandardCase: Mur de base:Int. plâtre 50 mm (3)
In: RDC
Type - PredefinedType: STANDARD; Material: Mur par défaut 5 cm
Pset_WallCommon - ExtendToStructure: yes; LoadBearing: no; IsExternal: no; Reference: Int. plâtre 50 mm
Name (Mur de base:Int. plâtre 50 mm:...)
456783
456873
456918

# IfcWallStandardCase: Mur de base:Int. plâtre 70 mm, Mur de base:Int. plâtre 70 mm:1092222
In: RDC
Type - PredefinedType: STANDARD; Material: Mur par défaut 7 cm
Pset_WallCommon - ExtendToStructure: yes; LoadBearing: no; IsExternal: no; Reference: Int. plâtre 70 mm

# IfcWallStandardCase: Mur de base:MET 4 + ISO 10 + MET 1 (4)
In: R+1
Type - PredefinedType: STANDARD; Material: Tôle/Doublage 4 cm, Laine minérale 9.5 cm, Tôle/Doublage 1.25 cm
Pset_WallCommon - ExtendToStructure: no; IsExternal: yes; LoadBearing: no; Reference: MET 4 + ISO 10 + MET 1; ThermalTransmittance: 0.357866 kg/K/s3
Name (Mur de base:MET 4 + ISO 10 + MET 1:...)
745847
745848
745849
745850

# IfcWallStandardCase: Mur de base:MET 4 + ISO 14 + PLA 2, Mur de base:MET 4 + ISO 14 + PLA 2:1096757
In: RDC
Material: Tôle/Doublage 4 cm, Laine minérale 14 cm, Plâtre 2 cm
Pset_WallCommon - LoadBearing: yes; IsExternal: yes; ExtendToStructure: yes; Reference: MET 4 + ISO 14 + PLA 2; ThermalTransmittance: 0.240556 kg/K/s3

# IfcWallStandardCase: Mur de base:MET 4 + ISO 16 + PLA 2 (6)
In: RDC
Type - PredefinedType: STANDARD; Material: Tôle/Doublage 4 cm, Laine minérale 16 cm, Plâtre 2 cm
Pset_WallCommon - ExtendToStructure: no; IsExternal: yes; Reference: MET 4 + ISO 16 + PLA 2; ThermalTransmittance: 0.210736 kg/K/s3
Name (Mur de base:MET 4 + ISO 16 + PLA 2:...) | LoadBearing
391658 | yes
391802 | no
391921 | no
1607771 | yes
1607772 | no
1607773 | no

# IfcWallStandardCase: Mur de base:MET 4 + ISO 6 + MET 1, Mur de base:MET 4 + ISO 6 + MET 1:1253706
In: RDC
Material: Tôle/Doublage 4 cm, Laine minérale 6 cm, Tôle/Doublage 1 cm
Pset_WallCommon - ExtendToStructure: no; IsExternal: yes; LoadBearing: no; Reference: MET 4 + ISO 6 + MET 1; ThermalTransmittance: 0.566597 kg/K/s3

# IfcWallStandardCase: Mur de base:MET 4 + ISO 8 + MET 4, Mur de base:MET 4 + ISO 8 + MET 4:532391
In: R+1
Type - PredefinedType: STANDARD; Material: Tôle/Doublage 4 cm, Laine minérale 8 cm, Tôle/Doublage 4 cm
Pset_WallCommon - ExtendToStructure: no; IsExternal: yes; LoadBearing: no; Reference: MET 4 + ISO 8 + MET 4; ThermalTransmittance: 0.424937 kg/K/s3

# IfcWallStandardCase: Mur de base:MET 4 + ISO 8 + PLA 2 (9)
Type - PredefinedType: STANDARD; Material: Tôle/Doublage 4 cm, Laine minérale 8 cm, Plâtre 2 cm
Pset_WallCommon - ExtendToStructure: no; IsExternal: yes; Reference: MET 4 + ISO 8 + PLA 2; ThermalTransmittance: 0.418002 kg/K/s3
Name (Mur de base:MET 4 + ISO 8 + PLA 2:...) | In | LoadBearing
405420 | RDC | no
482494 | R+1 | yes
483044 | R+1 | yes
488723 | RDC | no
507472 | R+1 | no
509468 | R+1 | no
782346 | R+1 | no
782347 | R+1 | no
1608141 | RDC | no

# IfcWallStandardCase: Mur de base:MET PROJET 4 + ISO 23 (4)
Material: Tôle/Doublage(PROJET) 4 cm, Laine minérale 23 cm
Pset_WallCommon - LoadBearing: yes; ExtendToStructure: no; IsExternal: yes; Reference: MET PROJET 4 + ISO 23; ThermalTransmittance: 0.147822 kg/K/s3
Name (Mur de base:MET PROJET 4 + ISO 23:...) | In
1748172 | RDC
1754406 | R+1
1767977 | R+1
1812783 | R+1

# IfcWallStandardCase: Mur de base:MET PROJET 4 + ISO 23 + MET 1 (7)
Material: Tôle/Doublage(PROJET) 4 cm, Laine minérale 22 cm, Tôle/Doublage(PROJET) 1 cm
Pset_WallCommon - IsExternal: yes; Reference: MET PROJET 4 + ISO 23 + MET 1; ThermalTransmittance: 0.15454 kg/K/s3
Name (Mur de base:MET PROJET 4 + ISO 23 + MET 1:...) | In | ExtendToStructure | LoadBearing
1088828 | R+1 | no | no
1204143 | Acrotère EXT2 | no | yes
1204153 | Acrotère EXT2 | no | yes
1241007 | Acrotère EXT2 | no | no
1241101 | Acrotère EXT2 | yes | no
1241160 | Acrotère EXT2 | yes | no
1291455 | Acrotère EXT1 | no | no

# IfcWallStandardCase: Mur de base:MET PROJET 4 + ISO 23 + MET 2 bis (2)
Type - PredefinedType: STANDARD; Material: Tôle/Doublage(PROJET) 4 cm, Laine minérale 22 cm, Plateau-acier-perforé 1 cm
Pset_WallCommon - ExtendToStructure: no; IsExternal: yes; Reference: MET PROJET 4 + ISO 23 + MET 2 bis; ThermalTransmittance: 0.15454 kg/K/s3
Name (Mur de base:MET PROJET 4 + ISO 23 + MET 2 bis:...) | In | LoadBearing
655870 | RDC | no
936827 | Acrotère EXT2 | yes

# IfcWallStandardCase: Mur de base:MET PROJET 6, Mur de base:MET PROJET 6:754558
In: RDC
Type - PredefinedType: STANDARD; Material: Tôle/Doublage(PROJET) 6 cm
Pset_WallCommon - ExtendToStructure: no; IsExternal: yes; LoadBearing: no; Reference: MET PROJET 6; ThermalTransmittance: 3833.33 kg/K/s3

# IfcWallStandardCase: Mur de base:PAR 15 (3)
In: RDC
Type - PredefinedType: STANDARD; Material: Maçonnerie 15 cm
Pset_WallCommon - ExtendToStructure: no; IsExternal: yes; LoadBearing: no; Reference: PAR 15; ThermalTransmittance: 8.66667 kg/K/s3
Name (Mur de base:PAR 15:...)
1604799
1604800
1604871

# IfcWallStandardCase: Mur de base:PAR 20 (7)
In: RDC
Type - PredefinedType: STANDARD; Material: Maçonnerie 20 cm
Pset_WallCommon - IsExternal: yes; Reference: PAR 20; ThermalTransmittance: 6.5 kg/K/s3
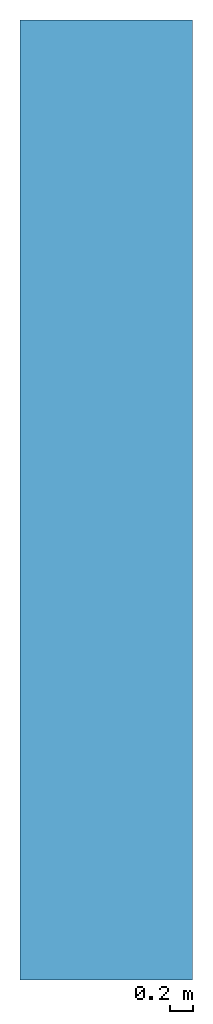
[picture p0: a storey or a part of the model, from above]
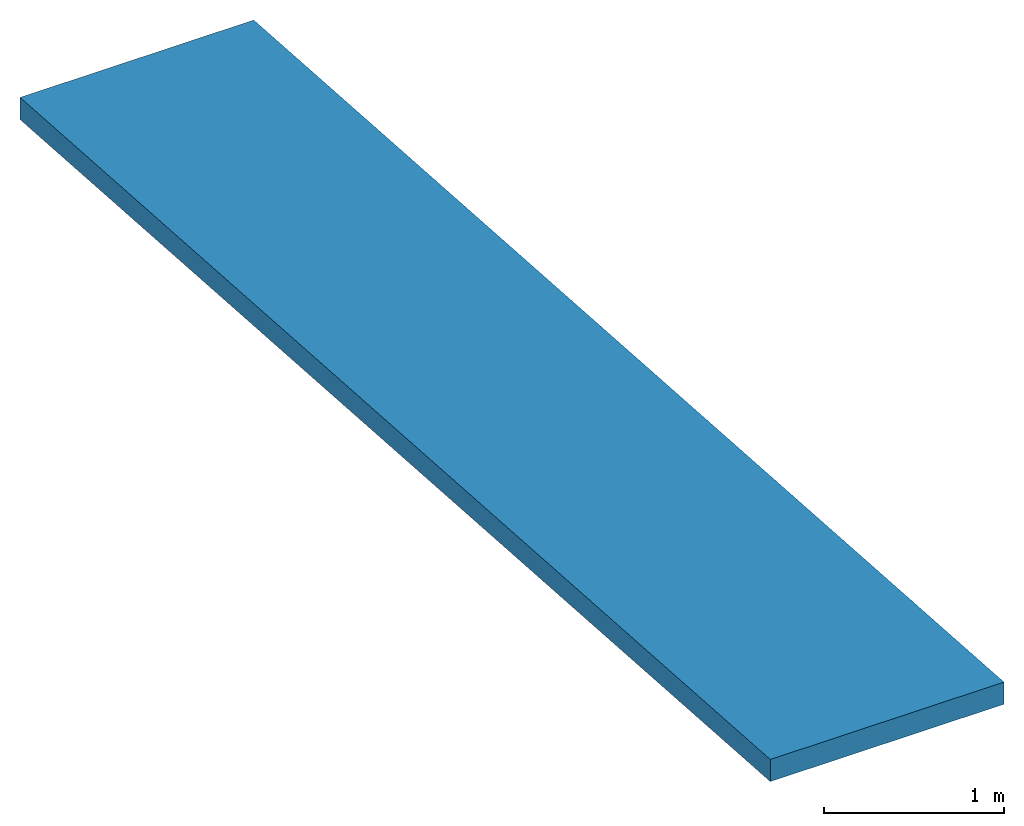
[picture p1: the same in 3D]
Properties of the parts of a building model (IFC2X3), part 3 of 3

# IfcWallStandardCase: Mur de base:PAR 20 (7)
Name (Mur de base:PAR 20:...) | LoadBearing | ExtendToStructure
376276 | yes | yes
1096480 | yes | no
1604796 | no | no
1604797 | no | no
1604798 | no | no
1604801 | no | no
1604804 | no | no

# IfcWallStandardCase: Mur de base:PLA 1 + PAR 20 + ISO 10 + PLA 1, Mur de base:PLA 1 + PAR 20 + ISO 10 + PLA 1:325169
In: RDC
Type - PredefinedType: STANDARD; Material: Plâtre 1 cm, Maçonnerie 20 cm, Laine minérale 10 cm, Plâtre 1 cm
Pset_WallCommon - LoadBearing: yes; ExtendToStructure: no; IsExternal: yes; Reference: PLA 1 + PAR 20 + ISO 10 + PLA 1; ThermalTransmittance: 0.319057 kg/K/s3

# IfcWallStandardCase: Mur de base:PLA 1.25 + ISO 9.5 + MET 4 (10)
In: RDC
Type - PredefinedType: STANDARD; Material: Tôle/Doublage 2 cm, Laine minérale 9.5 cm, Plâtre_MU 1.25 cm
Pset_WallCommon - IsExternal: yes; LoadBearing: no; Reference: PLA 1.25 + ISO 9.5 + MET 4; ThermalTransmittance: 0.354772 kg/K/s3
Name (Mur de base:PLA 1.25 + ISO 9.5 + MET 4:...) | ExtendToStructure
743892 | no
744185 | yes
744683 | no
744847 | no
744849 | no
745227 | no
745229 | no
745297 | no
745299 | no
745300 | no

# IfcWallStandardCase: Mur de base:PLA 10 (33)
Type - PredefinedType: STANDARD; Material: Plâtre 10 cm
Pset_WallCommon - LoadBearing: no; IsExternal: no; ThermalTransmittance: 5.1 kg/K/s3; Reference: PLA 10
Name (Mur de base:PLA 10:...) | In | ExtendToStructure
620084 | RDC | yes
621274 | RDC | yes
621686 | RDC | yes
622499 | RDC | yes
623288 | RDC | yes
624634 | RDC | yes
628136 | RDC | yes
628224 | RDC | yes
628448 | RDC | yes
651201 | RDC | yes
759497 | RDC | yes
759589 | RDC | yes
843691 | RDC | no
844469 | RDC | no
844497 | RDC | no
1134161 | RDC | yes
1400748 | R+1 | no
1400780 | R+1 | no
1483645 | RDC | no
1483706 | RDC | no
1517618 | RDC | yes
1529206 | R+1 | no
1529258 | R+1 | no
1573874 | RDC | no
1575711 | RDC | yes
1575712 | RDC | yes
1575713 | RDC | yes
1575714 | RDC | yes
1575721 | RDC | yes
1577393 | RDC | no
1631376 | R+1 | no
1631377 | R+1 | no
1631713 | R+1 | no

# IfcWallStandardCase: Mur de base:PLA 12 (4)
Type - PredefinedType: STANDARD; Material: Plâtre 12 cm
Pset_WallCommon - LoadBearing: no; IsExternal: no; Reference: PLA 12; ThermalTransmittance: 4.25 kg/K/s3
Name (Mur de base:PLA 12:...) | In | ExtendToStructure
1601901 | RDC | yes
1602103 | RDC | yes
1628703 | R+1 | no
1631306 | R+1 | no

# IfcWallStandardCase: Mur de base:PLA 2 + + ISO 9 + ETAN 1 (7)
Type - PredefinedType: STANDARD; Material: Maçonnerie 1 cm, Laine minérale 9 cm, Plâtre 2 cm
Pset_WallCommon - ExtendToStructure: no; IsExternal: yes; LoadBearing: no; Reference: PLA 2 + + ISO 9 + ETAN 1; ThermalTransmittance: 0.3712 kg/K/s3
Name (Mur de base:PLA 2 + + ISO 9 + ETAN 1:...) | In
1725926 | RDC
1728600 | RDC
1734228 | RDC
2037070 | RDC
2037194 | RDC
2041356 | Acrotère EXT2
2068155 | R+1

# IfcWallStandardCase: Mur de base:PLA 2 + PAR 20 (6)
In: RDC
Type - PredefinedType: STANDARD; Material: Plâtre 2 cm, Maçonnerie 20 cm
Pset_WallCommon - LoadBearing: yes; IsExternal: yes; ExtendToStructure: yes; Reference: PLA 2 + PAR 20; ThermalTransmittance: 5.17969 kg/K/s3
Name (Mur de base:PLA 2 + PAR 20:...)
339847
339944
340049
651968
668138
1096730

# IfcWallStandardCase: Mur de base:PLA 5 (29)
Type - PredefinedType: STANDARD; Material: Plâtre 5 cm
Pset_WallCommon - LoadBearing: no; IsExternal: no; Reference: PLA 5; ThermalTransmittance: 10.2 kg/K/s3
Name (Mur de base:PLA 5:...) | In | ExtendToStructure
622965 | RDC | no
1057938 | RDC | no
1057993 | RDC | no
1254089 | RDC | yes
1254120 | RDC | yes
1254386 | RDC | yes
1254464 | RDC | yes
1254465 | RDC | yes
1254662 | RDC | no
1254754 | RDC | yes
1254755 | RDC | yes
1254763 | RDC | no
1254764 | RDC | no
1254792 | R+1 | no
1254793 | R+1 | no
1254794 | R+1 | no
1254795 | R+1 | no
1254913 | RDC | yes
1254914 | RDC | yes
1526415 | RDC | yes
1615031 | R+1 | no
2000807 | R+1 | no
2000808 | R+1 | no
2001371 | R+1 | no
2001425 | R+1 | no
2001499 | RDC | no
2001500 | RDC | no
2001958 | RDC | no
2001959 | RDC | no

# IfcWallStandardCase: Mur de base:PLA 7 (14)
In: RDC
Type - PredefinedType: STANDARD; Material: Plâtre 7 cm
Pset_WallCommon - LoadBearing: no; IsExternal: no; Reference: PLA 7; ThermalTransmittance: 7.28571 kg/K/s3
Name (Mur de base:PLA 7:...) | ExtendToStructure
623731 | yes
626651 | yes
1496975 | yes
1497682 | no
1574251 | yes
1574295 | no
1575720 | yes
1579500 | yes
1579557 | yes
1592651 | yes
1602305 | yes
1603406 | no
2168435 | no
2168454 | no

# IfcWallStandardCase: Mur de base:PLA EXISTANT 10 (9)
Type - PredefinedType: STANDARD; Material: Plâtre EXISTANT 10 cm
Pset_WallCommon - LoadBearing: no; IsExternal: no; ThermalTransmittance: 5.1 kg/K/s3; Reference: PLA EXISTANT 10
Name (Mur de base:PLA EXISTANT 10:...) | In | ExtendToStructure
1114597 | RDC | no
1590113 | RDC | yes
1601122 | RDC | yes
1601123 | RDC | yes
1604326 | RDC | yes
1607763 | RDC | yes
1631710 | R+1 | no
1631711 | R+1 | no
1631714 | R+1 | no

# IfcWallStandardCase: Mur de base:PLA EXISTANT 5 (8)
Type - PredefinedType: STANDARD; Material: Plâtre EXISTANT 5 cm
Pset_WallCommon - LoadBearing: no; IsExternal: no; Reference: PLA EXISTANT 5; ThermalTransmittance: 10.2 kg/K/s3
Name (Mur de base:PLA EXISTANT 5:...) | In | ExtendToStructure
1590356 | RDC | yes
1590357 | RDC | yes
1601567 | RDC | yes
1601568 | RDC | yes
1601569 | RDC | yes
1601570 | RDC | yes
1898731 | R+1 | no
1898732 | R+1 | no

# IfcWallStandardCase: Mur de base:PLA EXISTANT 7 (19)
In: RDC
Type - PredefinedType: STANDARD; Material: Plâtre EXISTANT 7 cm
Pset_WallCommon - Reference: PLA EXISTANT 7; LoadBearing: no; IsExternal: no; ThermalTransmittance: 7.28571 kg/K/s3
Name (Mur de base:PLA EXISTANT 7:...) | ExtendToStructure
329089 | yes
329286 | yes
329547 | yes
332270 | yes
361836 | yes
363011 | yes
1372550 | no
1372551 | no
1372552 | no
1372553 | no
1372554 | no
1590366 | no
1602304 | yes
1602307 | yes
1602308 | yes
1602311 | yes
1602511 | yes
1604170 | yes
1607761 | yes

# IfcWallStandardCase: Mur de base:STRAT 2 (6)
In: RDC
Type - PredefinedType: STANDARD; Material: Stratifié, ivoire, mat 2 cm
Pset_WallCommon - ExtendToStructure: no; LoadBearing: no; IsExternal: no; Reference: STRAT 2; ThermalTransmittance: 10.45 kg/K/s3
Name (Mur de base:STRAT 2:...)
1134392
1135035
1135072
1575304
1575306
1575484

# IfcWindow: 1000mm x 1000mm (13)
In: Acrotère E3
Type - ParameterTakesPrecedence: no; Sizeable: no; Material: Verre, Métal - Aluminium
OverallHeight: 1062.59 cm; OverallWidth: 124.715 cm
Pset_WindowCommon - IsExternal: yes; Reference: 1000mm x 1000mm; ThermalTransmittance: 3.6886 kg/K/s3
Name (Skydome:1000mm x 1000mm:...)
964040
964041
964042
964043
964044
964045
964046
964047
964048
964049
964050
964051
1502396

# IfcWindow: 2B_70x115-I_150x40, 2B_70x115-I_150x40:2B_70x115-I_150x40:493820
In: RDC
Type - ParameterTakesPrecedence: no; Sizeable: no; Material: Verre
OverallHeight: 150 cm; OverallWidth: 150 cm
Pset_WindowCommon - IsExternal: yes; Reference: 2B_70x115-I_150x40

# IfcWindow: 2C_90x115-F_90x115, 2C_90x115-F_90x115:2C_90x115-F_90x115:474866
In: RDC
Type - ParameterTakesPrecedence: no; Sizeable: no; Material: Verre
OverallHeight: 150 cm; OverallWidth: 300 cm
Pset_WindowCommon - IsExternal: yes; Reference: 2C_90x115-F_90x115

# IfcWindow: 2F_90x115-2S_90x115-A_40, 2F_90x115-2S_90x115-A_40:2F_90x115-2S_90x115-A_40:1102022
In: R+1
Type - ParameterTakesPrecedence: no; Sizeable: no
OverallHeight: 140 cm; OverallWidth: 360 cm
Pset_WindowCommon - IsExternal: yes; Reference: 2F_90x115-2S_90x115-A_40

# IfcWindow: 2x2S_90x115-F90x115-A_40, 2x2S_90x115-F90x115-A_40:2x2S_90x115-F90x115-A_40:522891
In: R+1
Type - ParameterTakesPrecedence: no; Sizeable: no; Material: Verre
OverallHeight: 140 cm; OverallWidth: 540 cm
Pset_WindowCommon - IsExternal: yes; Reference: 2x2S_90x115-F90x115-A_40

# IfcWindow: 2xC_200x115-I_200x40, 2xC_200x115-I_200x40:2xC_200x115-I_200x40:505998
In: RDC
Type - ParameterTakesPrecedence: no; Sizeable: no; Material: Verre
OverallHeight: 155 cm; OverallWidth: 410 cm
Pset_WindowCommon - IsExternal: yes; Reference: 2xC_200x115-I_200x40

# IfcWindow: 600mm x 600mm, Skydome:600mm x 600mm:1520596
In: Acrotère E3
Type - ParameterTakesPrecedence: no; Sizeable: no; Material: Verre, Métal - Aluminium
OverallHeight: 1062.59 cm; OverallWidth: 104.715 cm
Pset_WindowCommon - IsExternal: yes; Reference: 600mm x 600mm; ThermalTransmittance: 3.6886 kg/K/s3

# IfcWindow: B_70x115, B_70x115:B_70x115:1091134
In: RDC
Type - ParameterTakesPrecedence: no; Sizeable: no; Material: Verre
OverallHeight: 115 cm; OverallWidth: 70 cm
Pset_WindowCommon - IsExternal: yes; Reference: B_70x115

# IfcWindow: B_90x115, B_90x115:B_90x115:473591
In: RDC
Type - ParameterTakesPrecedence: no; Sizeable: no; Material: Verre
OverallHeight: 115 cm; OverallWidth: 90 cm
Pset_WindowCommon - IsExternal: yes; Reference: B_90x115

# IfcWindow: C_200x115-I_200x40, C_200x115-I_200x40:C_200x115-I_200x40:463455
In: RDC
Type - ParameterTakesPrecedence: no; Sizeable: no; Material: Verre
OverallHeight: 155 cm; OverallWidth: 200 cm
Pset_WindowCommon - IsExternal: yes; Reference: C_200x115-I_200x40

# IfcWindow: MR 1 OB (34)
Type - ParameterTakesPrecedence: no; Sizeable: no; Material: PVC - Blanc, Fenêtre - Vitrage
Pset_WindowCommon - IsExternal: no; Reference: MR 1 OB; ThermalTransmittance: 3.6886 kg/K/s3
Name (MR 1 OB:MR 1 OB:...) | In | OverallHeight (cm) | OverallWidth (cm)
714740 | RDC | 160 | 101 | Group: Groupe de modèles:fc-est-men-01:714451
714830 | RDC | 160 | 101 | Group: Groupe de modèles:fc-est-men-01:714451
715134 | RDC | 160 | 101 | Group: Groupe de modèles:fc-est-men-01:714451
715278 | RDC | 160 | 101 | Group: Groupe de modèles:fc-est-men-01:714451
715400 | RDC | 160 | 101 | Group: Groupe de modèles:fc-est-men-01:714451
715672 | RDC | 160 | 101 | Group: Groupe de modèles:fc-est-men-01:714451
715735 | RDC | 160 | 101 | Group: Groupe de modèles:fc-est-men-01:714451
716142 | RDC | 160 | 101 | Group: Groupe de modèles:fc-est-men-01:714451
717496 | RDC | 165 | 101
718994 | RDC | 165 | 101
719292 | RDC | 165 | 101
719456 | RDC | 165 | 101
733499 | R+1 | 160 | 101 | Group: Groupe de modèles:fc-est-men-04:733328
733423 | R+1 | 160 | 101 | Group: Groupe de modèles:fc-est-men-04:733328
733680 | R+1 | 160 | 101 | Group: Groupe de modèles:fc-est-men-04:733672
733676 | R+1 | 160 | 101 | Group: Groupe de modèles:fc-est-men-04:733672
2076363 | R+1 | 243 | 189.625 | Group: Groupe de modèles:shed2:1363791
2159089 | R+1 | 243 | 189.625 | Group: Groupe de modèles:shed2:1363791
2076252 | R+1 | 243 | 189.625 | Group: Groupe de modèles:shed2:1363791
2158983 | R+1 | 243 | 189.625 | Group: Groupe de modèles:shed2:1363791
2002733 | R+1 | 316.984 | 189.625
1363083 | R+1 | 316.984 | 189.608
1744601 | R+1 | 160 | 101
1744597 | R+1 | 160 | 101
1744627 | R+1 | 160 | 101
1744623 | R+1 | 160 | 101
1744653 | R+1 | 160 | 101
1744649 | R+1 | 160 | 101
1745374 | R+1 | 160 | 101
1745370 | R+1 | 160 | 101
1745400 | R+1 | 160 | 101
1745396 | R+1 | 160 | 101
1745426 | R+1 | 160 | 101
1745422 | R+1 | 160 | 101

# IfcWindow: S_150x115_A_40 (2)
In: R+1
Type - ParameterTakesPrecedence: no; Sizeable: no; Material: Verre
OverallHeight: 144.5 cm; OverallWidth: 150 cm
Pset_WindowCommon - IsExternal: yes; Reference: S_150x115_A_40
Name (S_150x115_A_40:S_150x115_A_40:...)
525267
525318

# IfcWindow: S_90x115-F_90x115-A_40, S_90x115-F_90x115-A_40:S_90x115-F_90x115-A_40:528114
In: R+1
Type - ParameterTakesPrecedence: no; Sizeable: no; Material: Verre
OverallHeight: 150 cm; OverallWidth: 180 cm
Pset_WindowCommon - IsExternal: yes; Reference: S_90x115-F_90x115-A_40

# IfcWindow: V_90x100-I_90x40 (13)
Type - ParameterTakesPrecedence: no; Sizeable: no; Material: Verre
OverallHeight: 170 cm; OverallWidth: 180 cm
Pset_WindowCommon - IsExternal: yes; Reference: V_90x100-I_90x40
Name (V_90x100-I_90x40:V_90x100-I_90x40:...) | In
469426 | RDC
470261 | R+1
526625 | R+1
528328 | Acrotère E1
1096453 | RDC
1096454 | RDC
1096455 | RDC
1096456 | R+1
1096457 | R+1
1608095 | RDC
1608096 | R+1
1608147 | R+1
1608148 | Acrotère E1
